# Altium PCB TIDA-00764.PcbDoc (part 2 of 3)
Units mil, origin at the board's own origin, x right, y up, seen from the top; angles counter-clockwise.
Board outline 6250 x 2150 mil, 4 copper layers (Top Layer, GND, VDD, Bottom Layer), stack 61.6 mil thick; 231 components, 137 nets, 687 pads, 247 vias.

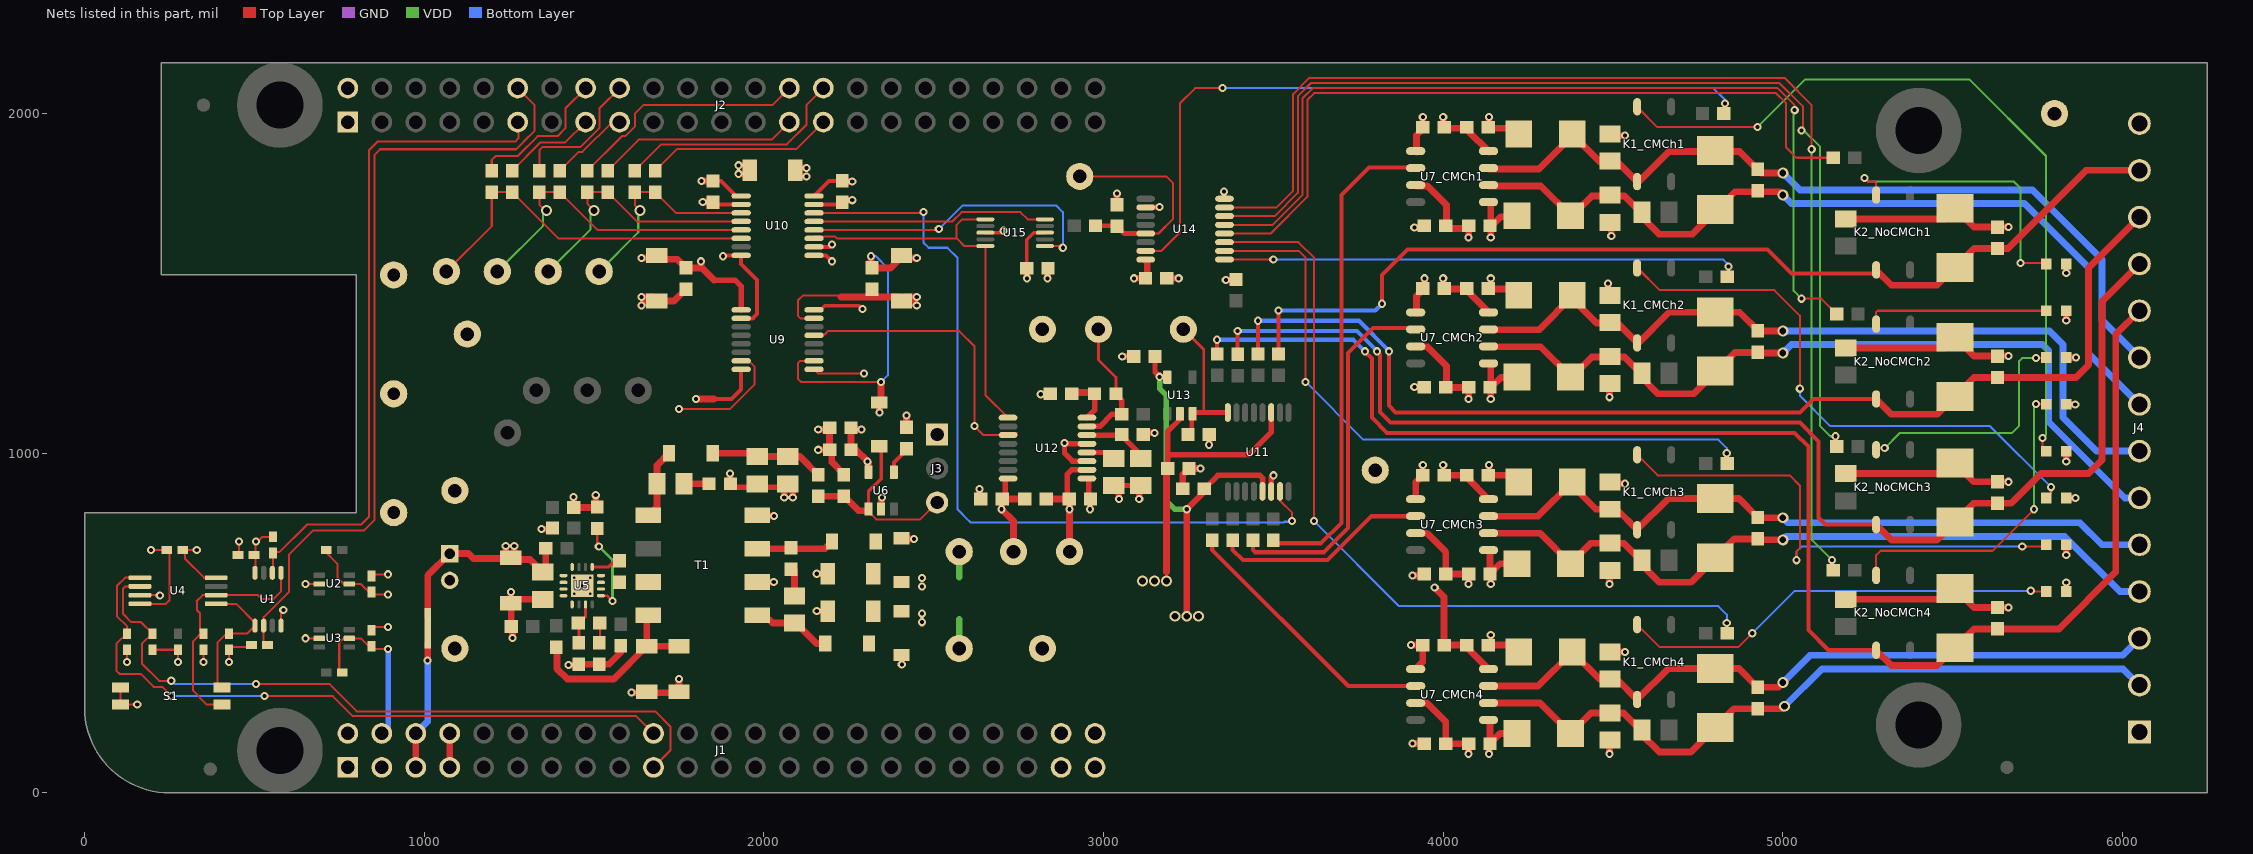
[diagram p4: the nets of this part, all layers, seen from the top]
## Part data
C1 C2 C3 C4: "CAP, CERM, 0.1 µF, 50 V, +/- 10%, X7R, 0402"
C5: "CAP, CERM, 1000 pF, 2000 V, +/- 10%, X7R, 1206_190"
C6: "CAP, AL, 47 µF, 35 V, +/- 20%, TH"
C7 C13 C14 C33 C34: "CAP, CERM, 22 µF, 10 V, +/- 10%, X7R, 1206"
C8 C18 C19 C47 C48: "CAP, CERM, 10 µF, 10 V, +/- 10%, X7R, 0805"
C9 C12: "CAP, CERM, 2.2 µF, 50 V, +/- 10%, X7R, 1206"
C10 C17 C35 C36 C37 C38 C49 C50 C51: "CAP, CERM, 0.1 µF, 16 V, +/- 10%, X7R, 0603"
C11 C23: "CAP, CERM, 15 pF, 50 V, +/- 5%, C0G/NP0, 0603"
C15 C16 C21: "CAP, CERM, 2.2 µF, 10 V, +/- 10%, X7R, 0603"
C20: "CAP, CERM, 0.033 µF, 50 V, +/- 10%, X7R, 0603"
C22: "CAP, CERM, 82 pF, 50 V, +/- 5%, C0G/NP0, 0603"
C24: "CAP, CERM, 0.01 µF, 16 V, +/- 10%, X7R, 0603"
C25_CMCh1 C25_CMCh2 C25_CMCh3 C25_CMCh4 C30_CMCh1 C30_CMCh2 C30_CMCh3 C30_CMCh4 C39 C44 C45: "CAP, CERM, 0.1 µF, 50 V, +/- 10%, X7R, 0603"
C26_CMCh1 C26_CMCh2 C26_CMCh3 C26_CMCh4 C31_CMCh1 C31_CMCh2 C31_CMCh3 C31_CMCh4 C40 C41 C46: "CAP, CERM, 1 µF, 16 V, +/- 10%, X7R, 0603"
C27_CMCh1 C27_CMCh2 C27_CMCh3 C27_CMCh4 C29_CMCh1 C29_CMCh2 C29_CMCh3 C29_CMCh4: "CAP, CERM, 1000 pF, 630 V, +/- 5%, X7R, 0805"
C28_CMCh1 C28_CMCh2 C28_CMCh3 C28_CMCh4 C32_NoCMCh1 C32_NoCMCh2 C32_NoCMCh3 C32_NoCMCh4: "CAP, CERM, 0.01 µF, 100 V, +/- 10%, X7R, 0603"
C42: "CAP, CERM, 100 pF, 50 V, +/- 5%, C0G/NP0, 0603"
C43: "CAP, CERM, 820 pF, 50 V, +/- 5%, C0G/NP0, 0603"
D1 D4: "Diode, Ultrafast, 100 V, 0.15 A, SOD-123"
D2 D3: "Diode, Zener, 16 V, 500 mW, SOD-123"
D5 D6: "Diode, Schottky, 30 V, 0.5 A, SOD-123"
D7_CMCh1 D7_CMCh2 D7_CMCh3 D7_CMCh4 D10_CMCh1 D10_CMCh2 D10_CMCh3 D10_CMCh4: "Diode, TVS, Bi, 160 V, 400 W, SMA"
D8_CMCh1 D8_CMCh2 D8_CMCh3 D8_CMCh4 D11_NoCMCh1 D11_NoCMCh2 D11_NoCMCh3 D11_NoCMCh4: "LED, Blue, SMD"
D9_CMCh1 D9_CMCh2 D9_CMCh3 D9_CMCh4 D12_NoCMCh1 D12_NoCMCh2 D12_NoCMCh3 D12_NoCMCh4: "Diode, TVS, Bi, 36 V, 600 W, SMB"
FID1 FID2 FID3: "Fiducial mark.  There is nothing to buy or mount."
J1 J2: "Female Connector, 2.54mm, 23x2, TH"
J3: "Header, 100mil, 3x1, Tin, TH"
J4: "Header (Shrouded), 3.5mm, 14x1, Tin, R/A, TH"
K1_CMCh1 K1_CMCh2 K1_CMCh3 K1_CMCh4 K2_NoCMCh1 K2_NoCMCh2 K2_NoCMCh3 K2_NoCMCh4: "Relay, SPST-NO (1 Form A), 0.1 A, 1.2 VDC, SMD"
Logo1: library part TI_Logo, "Texas Instrument Corporate Signature"
Logo2: library part Pb-Free
MH1 MH2 MH3 MH4: library part "Mounting Hole (Imperial) with Pads", "PCB Mounting Hole"
NT1: "Single point connection between nets."
R1 R2 R3 R4 R13 R14 R15: "RES, 47 k, 5%, 0.063 W, 0402"
R5 R6 R7 R8 R9 R10 R11 R12 R24 R33 R41 R42: "RES, 0, 5%, 0.1 W, 0603"
R16 R17: "RES, 6.65 k, 1%, 0.063 W, 0402"
R18 R26: "RES, 1.0 k, 5%, 0.125 W, 0805"
R19 R27: "RES, 10 k, 5%, 0.1 W, 0603"
R20: "RES, 220 k, 5%, 0.1 W, 0603"
R21: "RES, 16.2 k, 1%, 0.1 W, 0603"
R22: "RES, 75 k, 5%, 0.1 W, 0603"
R23: "RES, 10.0 k, 1%, 0.1 W, 0603"
R25: "RES, 240 k, 5%, 0.1 W, 0603"
R28_CMCh1 R28_CMCh2 R28_CMCh3 R28_CMCh4 R30_NoCMCh1 R30_NoCMCh2 R30_NoCMCh3 R30_NoCMCh4: "RES, 49.9, 1%, 0.1 W, 0603"
R29_CMCh1 R29_CMCh2 R29_CMCh3 R29_CMCh4 R31_NoCMCh1 R31_NoCMCh2 R31_NoCMCh3 R31_NoCMCh4: "RES, 200, 0.1%, 0.125 W, 0805"
R32 R34 R35 R36 R37 R38 R39 R40: "RES, 5.11 k, 1%, 0.1 W, 0603"
R43: "RES, 100 k, 5%, 0.1 W, 0603"
R44: "RES, 47 k, 5%, 0.1 W, 0603"
S1: "Switch, SPST, Off-On, 2 Pos, SMD"
SH-J1: "Shunt, 2.54mm, Gold, Black"
T1: "Transformer, 2.7 uH, SMT"
TP1 TP2 TP3: "TEST POINT.  No entry in BOM."
TP4 TP5 TP7 TP8: "Test Point, Miniature, Red, TH"
TP6 TP9 TP10 TP11 TP12 TP24: "Test Point, Miniature, Black, TH"
TP13 TP14 TP15 TP16 TP17 TP18 TP19 TP20 TP22 TP23 TP25: "Test Point, Miniature, Yellow, TH"
TP21: "Test Point, Miniature, Orange, TH"
U1: "Dual 2-Input Exclusive-OR Gate, DCT0008A"
U2 U3: "Single 3-Input Positive-OR Gate, DCK0006A"
U4: "256K I2C CMOS Serial EEPROM, TSSOP-8"
U5: "2.95V To 6V Input, 2W, Isolated DC/DC Converter with Integrated FETs, RTE0016C"
U6: "150-mA Low-noise Low-dropout Regulator With Shutdown, DBV0005A"
U7_CMCh1 U7_CMCh2 U7_CMCh3 U7_CMCh4: "High Common-Mode Voltage Difference Amplifier, D0008A"
U9 U10: "4242-VPK Small-Footprint and Low-Power Quad Channels Digital Isolators, DBQ0016A"
U11: "Fault-Protected, 8-Channel, Single-Ended Multiplexer, PW0016A"
U12: "SAR ADC with 16 Bits, Single Channel, 1MSPS, and Bipolar Inputs off +5 V Supply, PW0016A"
U13: "36-V, Precision, Rail-to-Rail Input/Output, Low Offset Voltage, Low Input Bias Current Op Amp with e-trim, DBV0005A"
U14: "8-Bit Shift Register With Output Registers, PW0016A"
U15: "DUAL 10-Ohm SPDT ANALOG SWITCH, DGS0010A"
ZZ1 ZZ2 ZZ3: library part AssemblyNote

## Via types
v1: diameter 24, hole 12, Top Layer to Bottom Layer, 201 vias
v2: diameter 39.37, hole 19.68, Top Layer to Bottom Layer, 24 vias
v3: diameter 32, hole 20, Top Layer to Bottom Layer, 17 vias
v4: diameter 19.68, hole 7.87, Top Layer to Bottom Layer, tented top, 5 vias

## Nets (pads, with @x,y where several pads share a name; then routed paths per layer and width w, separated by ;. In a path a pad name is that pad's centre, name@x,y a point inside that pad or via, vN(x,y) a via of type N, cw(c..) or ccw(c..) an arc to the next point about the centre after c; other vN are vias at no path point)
+5V: C6.1 C7.1 C8.2 C33.1 C35.1 C37.1 NT1.2 R19.2 R20.2 TP4.1 U5.1 U5.2 U5.16 U9.1 U9.7 U10.1 | length 1545.7
  Top Layer w6: v1@1750,1134.2 v1(1750,1130) 1899.29,1130 1972.45,1203.15 1972.45,1254.83 1955.21,1272.07 U9.7@1933.03,1272.07
  Top Layer w12: C37.1@1850.32,1801.5 1873.5,1801.5 1917.5,1757.5 U10.1@1933.03,1757.5
  Top Layer w16: 1853.31,1509.57 1915.43,1509.57 1933.03,1491.97 U9.1@1933.03,1422.07
  Top Layer w20: NT1.2@1010,520 1010,639.37 C6.1@1075,704.37 1130.63,704.37 1145,690 C7.1@1244.73,690 ; C7.1@1239.87,701.11 v1(1239.87,726.38) ; C7.1@1253.9,687.09 1311.81,687.09 C8.2@1348.9,650 ; C7.1@1264.87,698.06 v1(1264.87,726.38) ; v1(1344.87,776.38) R19.2@1373.78,776.38 ; C8.2@1357.4,658.5 R20.2@1357.4,720 ; v1(1640,1575) 1673.97,1575 1677.63,1571.34 1744.72,1571.34 C35.1@1770.32,1545.75 1817.13,1545.75 1853.31,1509.57 ; 1815,1547.88 v1(1815,1565) ; v1(1816.5,1801.5) C37.1@1850.32,1801.5
+5V_ISO: C15.1 C16.1 C34.1 C36.1 C38.1 C40.1 C49.1 C50.1 D5.2 R33.1 R43.2 TP8.1 U6.5 U9.10 U9.16 U10.10 U10.16 U12.16 U14.10 U14.16 U15.8 | length 2170.3
  Top Layer w6: U9.10@2147.6,1272.07 2107.5,1272.07 2100,1264.57 2100,1219.57 2110,1209.57 2227.32,1209.57 v1(2345,1209.57)
  Top Layer w10: U9.16@2147.6,1422.07 2167.07,1422.07 2179.25,1434.25 2280.75,1434.25 v1(2290,1425) ; C49.1@2773.5,1545 2773.5,1628.5 2794.37,1649.37 U15.8@2827.28,1649.37
  Top Layer w12: U10.10@2147.6,1607.5 2192.5,1607.5 v1(2200,1615) ; U10.16@2147.6,1757.5 2191.91,1801.81 C38.1@2230.32,1801.81
  Top Layer w16: C40.1@2710,873.5 U12.16@2710,925 ; U14.10@3123.86,1723.66 3163.66,1723.66 v1(3165,1725)
  Top Layer w20: C38.1@2232.13,1800 v1(2260,1800) ; C16.1@2256.5,1071.32 2256.5,1011.32 2270.33,1011.32 2305,976.65 v1(2305,975) 2307.91,972.09 U6.5@2307.91,944.13 ; C16.1@2257.8,1070.02 v1(2287.4,1070.02) ; C36.1@2315,1549.02 v1(2315,1580) ; C36.1@2318.27,1545.75 2372.68,1545.75 2401.93,1575 v1(2450,1575) ; v1(2340,1119.86) D5.2@2340,1149.47 2345,1154.47 v1(2345,1209.57) ; C40.1@2698.05,865 R33.1@2768.5,865 ; C40.1@2700,865 v1(2700,835) 2735,800 TP8.1@2735,710 ; v1(2775,1515) C49.1@2775,1543.5 ; v1(3090,1515) C50.1@3119.8,1515 ; U14.16@3125,1565.59 3128.5,1562.09 C50.1@3128.5,1506.3 ; v1(3360,1510) 3388.5,1510 R43.2@3390,1511.5
  Bottom Layer w6: v1(2315,1580) 2330,1580 2365,1545 2365,1229.57 v1(2345,1209.57)
+5V_JACK: J1.5 J1.6 NT1.1 | length 379.5
  Top Layer w20: J1.5@975,75 J1.6@975,175 ; v1(1010,390) NT1.1@1010,440
  Bottom Layer w20: J1.6@975,175 1010,210 v1(1010,390)
+5V_JACK_USB: J1.7 J1.8 | length 100
  Top Layer w20: J1.7@1075,75 J1.8@1075,175
+15V_ISO: C9.1 C30_CMCh1.2 C30_CMCh2.2 C30_CMCh3.2 C30_CMCh4.2 C31_CMCh1.1 C31_CMCh2.1 C31_CMCh3.1 C31_CMCh4.1 C44.1 C45.2 D1.1 D2.1 TP5.1 U7_CMCh1.7 U7_CMCh2.7 U7_CMCh3.7 U7_CMCh4.7 U11.13 U13.5 | length 2338.2
  Top Layer w6: C30_CMCh4.2@4074.76,144.51 C30_CMCh4.2@4075,144.28
  Top Layer w16: C44.1@3151.5,1285 3151.5,1238.5 v1(3165,1225) 3186.73,1225 U13.5@3187.6,1224.13 ; C45.2@3296.5,895 3336.5,935 3460,935 3468.11,926.89 U11.13@3468.11,887.4
  Top Layer w20: v3(3245,520) v1(3245,835) 3296.5,886.5 C45.2@3296.5,895 ; U7_CMCh4.7@3918.98,264.51 3951.75,264.51 4007.76,208.5 C31_CMCh4.1@4007.76,144.51 C30_CMCh4.2@4074.76,144.51 ; U7_CMCh3.7@3918.98,764.51 3951.75,764.51 4007.76,708.5 C31_CMCh3.1@4007.76,644.51 C30_CMCh3.2@4074.76,644.51 ; U7_CMCh2.7@3921.2,1313.23 3953.97,1313.23 4009.98,1257.22 4009.98,1193.23 C30_CMCh2.2@4076.98,1193.23 ; U7_CMCh1.7@3921.2,1786.5 3953.97,1786.5 4009.98,1730.49 C31_CMCh1.1@4009.98,1666.5 ; C31_CMCh1.1@4009.98,1661.5 C30_CMCh1.2@4076.98,1661.5 ; v1(4075,115) C30_CMCh4.2@4075,144.28 ; v1(4075,615) C30_CMCh3.2@4075,644.28 ; v1(4075,1160) 4075,1185.21 C30_CMCh2.2@4080,1190.21 ; v1(4075,1635) 4075,1658.48 C30_CMCh1.2@4080,1663.48
  VDD w16: v1(3165,1225) 3165,1190 3185,1170 3185,860 3210,835 v1(3245,835)
  VDD w20: TP5.1@2575,425 2575,510
  other v1: 2465.98,502.52 2465.98,527.52
  other v3: 3210,520 3280,520
-15V_ISO: C12.2 C25_CMCh1.1 C25_CMCh2.1 C25_CMCh3.1 C25_CMCh4.1 C26_CMCh1.2 C26_CMCh2.2 C26_CMCh3.2 C26_CMCh4.2 C39.2 D3.2 D4.2 TP7.1 U7_CMCh1.4 U7_CMCh2.4 U7_CMCh3.4 U7_CMCh4.4 U11.3 U13.2 | length 1895.9
  Top Layer w6: C25_CMCh2.1@4000,1489.69 C25_CMCh2.1@4004.98,1484.72 ; C25_CMCh1.1@4000.5,1962.46 4005.98,1956.99 C25_CMCh1.1@4008.48,1954.48
  Top Layer w16: v3(3150,623.78) v3@3155,623.78 ; C39.2@3188.5,955 3188.5,1063.5 3225,1100 U13.2@3225,1115.87 ; 3190,995 3427.09,995 3493.7,1061.61 U11.3@3493.7,1119.68
  Top Layer w20: 3185,650 3185,951.5 C39.2@3188.5,955 ; v1(3975,605) 4002.76,577.24 C25_CMCh4.1@4002.76,435 C26_CMCh4.2@4069.76,435 4069.76,428.29 U7_CMCh4.4@4133.54,364.51 ; C25_CMCh3.1@4000,937.76 v1(4000,965) ; v1(4000,1515) 4000,1488.74 C25_CMCh2.1@4005,1483.74 ; C25_CMCh1.1@4000,1961.96 v1(4000,1990) ; C25_CMCh3.1@4002.76,935 C26_CMCh3.2@4069.76,935 4069.76,928.29 U7_CMCh3.4@4133.54,864.51 ; C25_CMCh2.1@4004.98,1483.72 4071.98,1483.72 4071.98,1477.01 U7_CMCh2.4@4135.76,1413.23 ; C25_CMCh1.1@4004.98,1956.99 4005.98,1956.99 4071.98,1956.99 4071.98,1950.28 U7_CMCh1.4@4135.76,1886.5
  VDD w20: 2575,635 TP7.1@2575,710
  other v1: 2465.98,607.52 2465.98,632.52
  other v3: 3115,623.78 3185,623.78
"A0 / SER": R7.2 R8.2 TP18.1 U10.5 | length 952.7
  Top Layer w6: v3(1360,1715) 1360,1710 1338.68,1731.32 R8.2@1338.68,1768.5 R7.2@1398.68,1768.5 1509.68,1657.5 U10.5@1933.03,1657.5
  VDD w6: TP18.1@1215,1535 1350,1670 1350,1705 v3(1360,1715)
"A0 / SER_ISO": U10.12 U15.6 | length 930.5
  Top Layer w6: U10.12@2147.6,1657.5 2512.5,1657.5 v1(2515,1660) ; U15.6@2827.28,1610 2875,1610 v1(2880,1605)
  Bottom Layer w6: v1(2515,1660) 2585,1730 2860,1730 2880,1710 v1(2880,1605)
"A1 / R\C\L\R\": R9.2 R10.2 TP19.1 U10.4 | length 786.4
  Top Layer w6: v3(1500,1715) 1480,1735 R10.2@1480,1768.5 R9.2@1540,1768.5 1626,1682.5 U10.4@1933.03,1682.5
  VDD w6: TP19.1@1365,1535 1490,1660 1490,1705 v3(1500,1715)
"A1 / R\C\L\R\_ISO": U10.13 U15.10 | length 699.4
  Top Layer w6: U10.13@2147.97,1682.87 2555.22,1682.87 2582.35,1710 2755,1710 2776.26,1688.74 U15.10@2827.28,1688.74
A2: R11.2 R12.2 TP20.1 U10.3 | length 627.7
  Top Layer w6: v3(1635,1715) 1620,1730 R12.2@1620,1768.5 R11.2@1680,1768.5 1741,1707.5 U10.3@1933.03,1707.5
  VDD w6: TP20.1@1515,1535 1630,1650 1630,1710 v3(1635,1715)
A2_ISO: U10.14 U11.15 | length 2377
  Top Layer w6: U10.14@2147.6,1707.5 2467.5,1707.5 v1(2470,1710) ; U11.15@3519.29,887.4 3519.29,860.71 3555,825 v1(3555,800)
  Bottom Layer w6: v1(2470,1710) 2470,1620 2485,1605 2540,1605 2570,1575 2570,835 2605,800 2605.38,800 2609.25,796.13 3530.75,796.13 3532.87,798.25 3553.25,798.25 v1(3555,800)
AVDD: C41.1 R33.2 TP21.1 U12.2 | length 354
  Top Layer w16: C41.1@2893.5,865 2893.5,938.5 2906.02,951.02 U12.2@2951.14,951.02
  Top Layer w20: R33.2@2831.5,865 C41.1@2893.5,865 ; C41.1@2898.5,865 2900,863.5 v1(2900,835) TP21.1@2900,710
CAPE_A0: J2.12 R1.2 U1.2 | length 2336.2
  Top Layer w6: U1.2@527.22,473.95 527.22,517.22 562.25,552.25 562.53,552.25 596.28,586 596.28,586.28 602.02,592.02 602.02,702.02 672.13,772.13 821.9,772.13 852.87,803.1 852.87,1877.87 870,1895 1270.5,1895 1292.87,1917.38 ; U1.2@527.2,492.24 527.2,446.42 R1.2@538.62,435 ; J2.12@1275,2075 1325,2025 1325,1950 1292.87,1917.87
CAPE_A1: J2.11 R3.2 U1.6 | length 1966.8
  Top Layer w6: U1.6@555,649.96 R3.2@555,706.38 557.2,708.58 573.58,708.58 655,790 814.5,790 837.2,812.71 837.2,1892.2 862.2,1917.2 1267.43,1917.2 1277.2,1926.98 J2.11@1277.2,1977.2
CH_IN+1: C32_NoCMCh1.1 D12_NoCMCh1.2 J4.13 K2_NoCMCh1.3 R40.2 | length 2975.3
  Top Layer w12: R40.2@3515,1292.07 v1(3515,1420) ; v1(3820,1440) 3820,1525 3895,1600 4955,1600 5025.24,1529.76 K2_NoCMCh1.3@5275,1529.76
  Top Layer w20: K2_NoCMCh1.3@5275,1539.76 5320.21,1494.55 5454.24,1494.55 D12_NoCMCh1.2@5507,1547.31 5562.51,1602.82 C32_NoCMCh1.1@5632,1602.82 5662.82,1602.82 5892.87,1832.87 J4.13@6050.04,1832.87
  Bottom Layer w12: v1(3515,1420) 3800,1420 v1(3820,1440)
CH_IN+2: C32_NoCMCh2.1 D12_NoCMCh2.2 J4.12 K2_NoCMCh2.3 R39.2 | length 3342.1
  Top Layer w12: R39.2@3455,1292.07 v1(3455,1390) ; v1(3840,1300) 3840,1140 3860,1120 5050,1120 5089.76,1159.76 K2_NoCMCh2.3@5275,1159.76
  Top Layer w20: K2_NoCMCh2.3@5275,1159.76 5320.21,1114.55 5454.24,1114.55 D12_NoCMCh2.2@5507,1167.31 5562.51,1222.82 C32_NoCMCh2.1@5632,1222.82 5862.82,1222.82 5900,1260 5900,1545.04 J4.12@6050.04,1695.08
  Bottom Layer w12: v1(3455,1390) 3751.59,1390 3840,1301.59 v1(3840,1300)
CH_IN+3: C32_NoCMCh3.1 D12_NoCMCh3.2 J4.11 K2_NoCMCh3.3 R38.2 | length 3820.6
  Top Layer w12: R38.2@3395,1292.07 v1(3395,1360) ; v1(3805,1300) 3814.13,1290.87 3814.13,1120.87 3845,1090 5050,1090 5105,1035 5105,810 5125.24,789.76 K2_NoCMCh3.3@5275,789.76
  Top Layer w20: K2_NoCMCh3.3@5275,789.76 5320.21,744.55 5454.24,744.55 D12_NoCMCh3.2@5507,797.31 5562.51,852.82 C32_NoCMCh3.1@5632,852.82 5672.82,852.82 5760,940 5900,940 5940,980 5940,1447.24 J4.11@6050.04,1557.28
  Bottom Layer w12: v1(3395,1360) 3746.59,1360 3805,1301.59 v1(3805,1300)
CH_IN+4: C32_NoCMCh4.1 D12_NoCMCh4.2 J4.10 K2_NoCMCh4.3 R37.2 | length 4414.3
  Top Layer w12: R37.2@3334.02,1293.05 v1(3334.02,1334.02) ; v1@3770,1298.41 3790,1278.41 3790,1105 3835,1060 3850,1060 5034.87,1060.13 5075,1020 5075,480 5135.24,419.76 K2_NoCMCh4.3@5275,419.76
  Top Layer w20: K2_NoCMCh4.3@5275,419.76 5320.21,374.55 5454.24,374.55 D12_NoCMCh4.2@5507,427.31 5562.51,482.82 C32_NoCMCh4.1@5632,482.82 5812.82,482.82 5980,650 5980,1349.45 J4.10@6050.04,1419.49
  Bottom Layer w12: v1(3334.02,1334.02) 3735.98,1334.02 v1(3770,1300)
CH_V/C_SWITCH1: R30_NoCMCh1.2 U14.4 | length 2285.3
  Top Layer w6: U14.4@3356.14,1646.89 3491.89,1646.89 3600,1755 3600,2040 3620,2060 4980,2060 5010,2030 5010,1900 5040,1870 R30_NoCMCh1.2@5148.5,1870
CH_V/C_SWITCH2: R30_NoCMCh2.2 U14.5 | length 2735.8
  Top Layer w6: U14.5@3356.14,1672.48 3497.86,1672.48 3586.13,1760.75 3586.13,2045.75 3615.38,2075 4984.62,2075 5035,2024.62 v1(5035,2010) ; v1(5055,1455) 5113.5,1455 R30_NoCMCh2.2@5158.5,1410
  VDD w6: v1(5035,2010) 5032.13,2007.13 5032.13,1477.87 v1(5055,1455)
CH_V/C_SWITCH3: R30_NoCMCh3.2 U14.6 | length 3114.7
  Top Layer w6: U14.6@3356.14,1698.07 3503.83,1698.07 3572.25,1766.49 3572.25,2051.49 3610.76,2090 4989.62,2090 5059.62,2020 5059.62,1954.62 v1(5055,1950) ; R30_NoCMCh3.2@5155,1023.5 v1(5155,1050)
  VDD w6: v1(5055,1950) 5062.35,1950 5110,1902.35 5110,1080 5140,1050 v1(5155,1050)
CH_V/C_SWITCH4: R30_NoCMCh4.2 U14.7 | length 3483.2
  Top Layer w6: U14.7@3356.14,1723.66 3509.8,1723.66 3558.38,1772.24 3558.38,2057.24 3606.14,2105 5005,2105 5085,2025 v1(5085,1895) ; v1(5145,685) 5145,658.5 R30_NoCMCh4.2@5148.5,655
  VDD w6: v1(5085,1895) 5085,745 v1(5145,685)
CMCH_IN+1: C27_CMCh1.1 C28_CMCh1.1 D7_CMCh1.1 D9_CMCh1.2 J4.9 K1_CMCh1.3 U7_CMCh1.3 | length 2407.6
  Top Layer w20: U7_CMCh1.3@4135.76,1836.5 4281.73,1836.5 4382.22,1936.99 4462.22,1856.99 4493.48,1856.99 4513.24,1856.99 4573.48,1796.75 4665,1888.27 4803.48,1888.27 4872.97,1888.27 4928.48,1832.76 4936.24,1825 v3(5000,1825)
  Bottom Layer w20: v3(5000,1825) 5050,1775 5735,1775 5940,1570 5940,1391.73 J4.9@6050.04,1281.69
CMCH_IN+2: C27_CMCh2.1 C28_CMCh2.1 D7_CMCh2.1 D9_CMCh2.2 J4.7 K1_CMCh2.3 U7_CMCh2.3 | length 2353.3
  Top Layer w20: U7_CMCh2.3@4135.76,1363.23 4281.73,1363.23 4382.22,1463.72 4382.22,1452.78 4451.28,1383.72 4493.48,1383.72 4513.24,1383.72 4573.48,1323.48 4665,1415 4803.48,1415 4872.97,1415 C28_CMCh2.1@4928.48,1359.49 ; C28_CMCh2.1@4928.99,1360 v3(5000,1360)
  Bottom Layer w20: v3(5000,1360) 5785,1360 5825,1320 5825,1105 5923.9,1006.1 J4.7@6050.04,1006.1
CMCH_IN+3: C27_CMCh3.1 C28_CMCh3.1 D7_CMCh3.1 D9_CMCh3.2 J4.5 K1_CMCh3.3 U7_CMCh3.3 | length 2116.2
  Top Layer w20: U7_CMCh3.3@4133.54,814.51 4279.51,814.51 D7_CMCh3.1@4380,915 4380,905 4450,835 C27_CMCh3.1@4491.26,835 4511.02,835 K1_CMCh3.3@4571.26,774.76 4662.78,866.28 D9_CMCh3.2@4801.26,866.28 4870.75,866.28 C28_CMCh3.1@4926.26,810.77 4927.03,810 v3(5000,810)
  Bottom Layer w20: v3(5000,810) 5015,795 5875,795 5939.49,730.51 J4.5@6050.04,730.51
CMCH_IN+4: C27_CMCh4.1 C28_CMCh4.1 D7_CMCh4.1 D9_CMCh4.2 J4.3 K1_CMCh4.3 U7_CMCh4.3 | length 2143.4
  Top Layer w20: U7_CMCh4.3@4133.54,314.51 4279.51,314.51 D7_CMCh4.1@4380,415 4460,335 C27_CMCh4.1@4491.26,335 4511.02,335 K1_CMCh4.3@4571.26,274.76 4662.78,366.28 D9_CMCh4.2@4801.26,366.28 4870.75,366.28 C28_CMCh4.1@4926.26,310.77 4985.77,310.77 v3(5000,325) v3@5006.54,325
  Bottom Layer w20: v3(5000,325) 5080,405 6000.12,405 J4.3@6050.04,454.92
CMCH_IN-1: C28_CMCh1.2 C29_CMCh1.2 D9_CMCh1.1 D10_CMCh1.1 J4.8 R29_CMCh1.1 U7_CMCh1.2 | length 2487.8
  Top Layer w20: U7_CMCh1.2@4135.76,1786.5 4287.22,1786.5 4377.22,1696.5 4437.71,1756.99 4493.48,1756.99 4533.48,1756.99 4583.48,1706.99 4583.48,1696.99 4635.47,1645 4734.22,1645 4803.48,1714.26 4858.99,1769.77 4928.48,1769.77 4990.23,1769.77 v3(5000,1760)
  Bottom Layer w20: v3(5000,1760) 5025,1735 5711.65,1735 5900,1546.65 5900,1293.94 J4.8@6050.04,1143.9
CMCH_IN-2: C28_CMCh2.2 C29_CMCh2.2 D9_CMCh2.1 D10_CMCh2.1 J4.6 R29_CMCh2.1 U7_CMCh2.2 | length 2398.9
  Top Layer w20: U7_CMCh2.2@4135.76,1313.23 4287.22,1313.23 4377.22,1223.23 4437.71,1283.72 4493.48,1283.72 4533.48,1283.72 4583.48,1233.72 4583.48,1223.72 4632.2,1175 4737.5,1175 4803.48,1240.98 4858.99,1296.5 4928.48,1296.5 4929.98,1295 v3(5000,1295)
  Bottom Layer w20: v3(5000,1295) 5025,1320 5765,1320 5782.39,1302.61 5782.39,1092.61 6006.69,868.31 J4.6@6050.04,868.31
CMCH_IN-3: C28_CMCh3.2 C29_CMCh3.2 D9_CMCh3.1 D10_CMCh3.1 J4.4 R29_CMCh3.1 U7_CMCh3.2 | length 2157.8
  Top Layer w20: U7_CMCh3.2@4133.54,764.51 4285,764.51 D10_CMCh3.1@4375,674.51 4435.49,735 C29_CMCh3.2@4491.26,735 4531.26,735 4581.26,685 4581.26,675 4636.26,620 4728.99,620 D9_CMCh3.1@4801.26,692.27 4856.77,747.78 C28_CMCh3.2@4926.26,747.78 4929.04,745 v3(5000,745)
  Bottom Layer w20: v3(5000,745) 5010,755 5830,755 5992.28,592.72 J4.4@6050.04,592.72
CMCH_IN-4: C28_CMCh4.2 C29_CMCh4.2 D9_CMCh4.1 D10_CMCh4.1 J4.2 R29_CMCh4.1 U7_CMCh4.2 | length 2153.6
  Top Layer w20: U7_CMCh4.2@4133.54,264.51 4285,264.51 D10_CMCh4.1@4375,174.51 4435.49,235 C29_CMCh4.2@4491.26,235 4531.26,235 4581.26,185 4581.26,175 4636.26,120 4728.99,120 D9_CMCh4.1@4801.26,192.27 4856.77,247.78 C28_CMCh4.2@4926.26,247.78 4997.78,247.78 v3(5005,255)
  Bottom Layer w20: v3(5005,255) 5115,365 6002.17,365 J4.2@6050.04,317.13
CMCH_OUT1: R36.2 U7_CMCh1.6 | length 1451.1
  Top Layer w12: R36.2@3496.63,742.05 3503.68,735 3640,735 3700,795 3700,1760 3781.5,1841.5 U7_CMCh1.6@3921.2,1841.5
CMCH_OUT2: R35.2 U7_CMCh2.6 | length 1087.4
  Top Layer w12: R35.2@3440,743.5 3440,715 3446.51,708.49 3648.49,708.49 3719.87,779.87 3719.87,1294.87 3793.23,1368.23 U7_CMCh2.6@3921.2,1368.23
CMCH_OUT3: R34.2 U7_CMCh3.6 | length 633.6
  Top Layer w12: R34.2@3380,743.5 3380,715 3410,685 3660,685 3789.51,814.51 U7_CMCh3.6@3918.98,814.51
CMCH_OUT4: R32.2 U7_CMCh4.6 | length 793.4
  Top Layer w12: R32.2@3320,743.5 3320,715 3720.49,314.51 U7_CMCh4.6@3918.98,314.51
CMCH_V/C_SWITCH1: R28_CMCh1.2 U14.15 | length 2182.4
  Top Layer w6: U14.15@3123.86,1595.71 3170.71,1595.71 3225,1650 3225,2030 3270,2075 v1(3350,2075) ; v1(4830,2030) 4830,2001.5 R28_CMCh1.2@4831.5,2000
  Bottom Layer w6: v1(3350,2075) 4795,2075 4830,2040 v1(4830,2030)
CMCH_V/C_SWITCH2: R28_CMCh2.2 U14.1 | length 1526.4
  Top Layer w6: U14.1@3356.14,1570.12 v1(3499.88,1570.12) ; R28_CMCh2.2@4836.5,1520 4840,1523.5 v1(4840,1550)
  Bottom Layer w6: v1@3500,1570 4825,1570 4840,1555 v1(4840,1550)
CMCH_V/C_SWITCH3: R28_CMCh3.2 U14.2 | length 1978.8
  Top Layer w6: U14.2@3356.14,1595.71 3574.29,1595.71 3595,1575 v1(3595,1210) ; v1(4835,1000) 4836.5,998.5 R28_CMCh3.2@4836.5,970
  Bottom Layer w6: v1(3595,1210) 3765,1040 4810,1040 4835,1015 v1(4835,1000)
CMCH_V/C_SWITCH4: R28_CMCh4.2 U14.3 | length 2442.6
  Top Layer w6: U14.3@3356.14,1621.3 3573.7,1621.3 3620,1575 v1(3620,800) ; v1(4835,500) 4836.5,498.5 R28_CMCh4.2@4836.5,470
  Bottom Layer w6: v1(3620,800) 3870,550 4810,550 4835,525 v1(4835,500)
CONVST/C\S\_ISO: U9.13 U12.11 | length 874
  Top Layer w6: U9.13@2147.6,1347.07 2150.53,1350 2180,1350 2190,1360 2226.89,1360 2227.32,1359.57 2575.43,1359.57 2620,1315 v1(2620,1080) 2646.61,1053.39 U12.11@2718.86,1053.39 2718.86,1059.24 2745.73,1059.24
DGND: C1.2 C2.2 C3.2 C4.2 C5.2 C6.2 C7.2 C8.1 C13.2 C14.2 C17.1 C22.1 C33.2 C35.2 C37.2 J1.1 J1.2 J1.43 J1.44 J1.45 J1.46 J2.1 J2.2 R22.1 R23.1 R25.1 R27.1 S1.1 S1.2 TP2.1 TP3.1 TP6.1 TP9.1 U1.4 U2.2 U3.2 U4.4 U4.7 U5.3 U5.4 U5.5 U5.17 U9.2 U9.8 U10.2 U10.8 | length 2159.8
  Top Layer w6: S1.1@105,310 S1.2@105,260 v1(155,260) v1@160.03,260 ; U4.7@162.8,582.2 212.2,582.2 220,590 221.35,588.65 v1(221.35,581.35) ; C4.2@288.62,715 295,708.65 295,690 351.61,633.39 U4.4@387.2,633.39 ; C4.2@296.53,715 v1(330,715) ; C1.2@455,693.62 v1(455,740) ; U1.4@578.39,492.37 578.39,528.51 585,535.13 v1(585,538.17) ; v1(649.98,614.99) U2.2@690.71,615 ; v1(650.73,455.01) U3.2@691.45,455.02 ; C3.2@845,478.64 854.9,488.52 v1(893.52,488.52) ; C2.2@845,638.62 849.9,643.52 v1@888.25,643.52 ; R23.1@1255.91,490 R23.1@1256.11,490 ; C22.1@1449.73,376.38 1454.73,381.38 C22.1@1456.11,380 ; R22.1@1453.9,847.8 R22.1@1454.87,848.77
  Top Layer w12: 1853.31,1159.57 1905,1159.57 1933.03,1187.6 U9.8@1933.03,1247.07 ; C37.2@1866.32,1732.5 U10.2@1933.03,1732.5 ; v1(1880,1580) 1882.5,1582.5 U10.8@1933.03,1582.5 1933.03,1557.06 1980,1510.09 1980,1410 1967.07,1397.07 U9.2@1933.03,1397.07
  Top Layer w20: C7.2@1254.87,570.52 v1(1254.87,591.38) ; R23.1@1256.11,490 C7.2@1256.11,569.29 ; C7.2@1256.81,570 C8.1@1348.9,570 ; v1(1259.87,456.38) R23.1@1259.87,486.03 ; v1(1424.87,376.38) C22.1@1449.73,376.38 ; R22.1@1439.87,840.52 v1(1439.87,871.38) ; R22.1@1440.4,840 1507.4,840 C17.1@1508.9,841.5 ; C22.1@1457.25,378.86 1544.65,378.86 1578.55,412.76 R25.1@1578.55,433.31 ; C17.1@1504.87,845.52 v1(1504.87,876.38) ; v1(1610,295) 1746.93,295 C14.2@1750,298.07 v1(1750,335) ; v1(1640,1435) 1653.07,1448.07 C33.2@1685,1448.07 1735.63,1448.07 C35.2@1770.32,1482.76 ; v1(1640,1460) C33.2@1673.07,1460 ; v1(1800,1160) 1852.88,1160 ; v1(1820,1740) C37.2@1838.82,1740 ; v1(1925,1822.64) C5.2@1948.07,1822.64 ; v1(1925,1847.64) C5.2@1943.07,1847.64
  other v1: 893.52,643.52
  other v4: 1441.38,586.38 1488.62,586.38 1465,610 1441.38,633.62 1488.62,633.62
DVDD: C1.1 C2.1 C3.1 C4.1 J1.3 J1.4 R1.1 R2.1 R3.1 R4.1 R13.1 R14.1 R15.1 R16.1 R17.1 TP1.1 U1.8 U2.5 U3.5 U4.8 | length 1522.4
  Top Layer w6: v1(125,385) R17.1@125.01,421.39 ; U4.8@162.8,556.61 238.86,556.61 249.87,567.63 249.87,715.01 C4.1@241.38,715 ; v1(195,715) C4.1@233.52,715.01 ; v1@275.01,377.89 R15.1@275.01,421.39 ; v1@350.02,377.89 R13.1@350.02,421.39 ; v1@425.02,377.89 R14.1@425.02,421.39 ; R14.1@425.02,429.27 477.77,429.27 R1.1@491.38,442.87 ; U1.8@503.62,649.89 503.62,700 503.62,733.62 523.62,753.62 R3.1@555,753.62 ; R2.1@703.52,715.01 745,673.53 745,633.25 749.69,628.57 758.38,619.84 763.24,615.01 813.52,615.01 845.02,583.52 v1(893.52,583.52) v1@895.02,585.01 ; R4.1@758.62,355 749.7,363.92 749.7,441.48 763.24,455.02 U3.5@779.31,455.02 813.52,455.02 845.02,423.52 v1(893.52,423.52)
  Top Layer w8: R16.1@200.01,421.39 R15.1@275.01,421.39
  Bottom Layer w16: J1.4@875,175 893.52,193.52 v1(893.52,423.52)
  other v1: 275,385 350,385 425,385 505,740
GND_ISO: C5.1 C9.2 C12.1 C15.2 C16.2 C18.2 C19.1 C21.2 C23.1 C24.2 C25_CMCh1.2 C25_CMCh2.2 C25_CMCh3.2 C25_CMCh4.2 C26_CMCh1.1 C26_CMCh2.1 C26_CMCh3.1 C26_CMCh4.1 C27_CMCh1.2 C27_CMCh2.2 C27_CMCh3.2 C27_CMCh4.2 C29_CMCh1.1 C29_CMCh2.1 C29_CMCh3.1 C29_CMCh4.1 C30_CMCh1.1 C30_CMCh2.1 C30_CMCh3.1 C30_CMCh4.1 C31_CMCh1.2 C31_CMCh2.2 C31_CMCh3.2 C31_CMCh4.2 C32_NoCMCh1.2 C32_NoCMCh2.2 C32_NoCMCh3.2 C32_NoCMCh4.2 C34.2 C36.2 C38.2 C39.1 C40.2 C41.2 C43.2 C44.2 C45.1 C46.2 C47.1 C48.1 C49.2 C50.2 C51.2 D2.2 D3.1 D7_CMCh1.2 D7_CMCh2.2 D7_CMCh3.2 D7_CMCh4.2 D8_CMCh1.2 D8_CMCh2.2 D8_CMCh3.2 D8_CMCh4.2 D10_CMCh1.2 D10_CMCh2.2 D10_CMCh3.2 D10_CMCh4.2 D11_NoCMCh1.2 D11_NoCMCh2.2 D11_NoCMCh3.2 D11_NoCMCh4.2 D12_NoCMCh1.1 D12_NoCMCh2.1 D12_NoCMCh3.1 D12_NoCMCh4.1 J3.1 J4.1 J4.14 R31_NoCMCh1.1 R31_NoCMCh2.1 R31_NoCMCh3.1 R31_NoCMCh4.1 R42.2 T1.5 T1.7 TP10.1 TP11.1 TP12.1 TP24.1 U6.2 U7_CMCh1.1 U7_CMCh1.5 U7_CMCh2.1 U7_CMCh2.5 U7_CMCh3.1 U7_CMCh3.5 U7_CMCh4.1 U7_CMCh4.5 U9.9 U9.15 U10.9 U10.15 U11.14 U12.1 U12.3 U12.5 U14.8 U15.3 | length 6913.6
  Top Layer w6: U9.9@2147.6,1247.07 2160.1,1234.57 v1(2295,1234.57) ; U9.15@2147.6,1397.07 2107.5,1397.07 2100,1404.57 2100,1449.57 2115.43,1465 2221.89,1465 2227.32,1459.57 ; C16.2@2184.47,1070.02 C16.2@2187.93,1066.56 ; C36.2@2330.63,1470.2 2340,1460.83 ; U6.2@2345.63,830.87 U6.2@2347.72,832.95 ; U11.14@3493.7,887.4 U11.14@3495,888.7 ; C25_CMCh1.2@3940,1958.97 C25_CMCh1.2@3941.98,1956.99 ; C26_CMCh4.1@4132.76,435 C26_CMCh4.1@4136.26,438.5 ; C26_CMCh3.1@4132.76,935 C26_CMCh3.1@4135,937.24 ; C30_CMCh4.1@4135,141.76 C30_CMCh4.1@4137.76,144.51 ; C26_CMCh2.1@4134.98,1483.72 C26_CMCh2.1@4138.48,1487.22
  Top Layer w10: U15.3@2652.09,1649.37 2699.37,1649.37 v1(2705,1655)
  Top Layer w12: U10.9@2147.6,1582.5 2182.5,1582.5 v1(2200,1565) ; U10.15@2147.6,1732.5 2224,1732.5 C38.2@2230.32,1738.82
  Top Layer w16: C23.1@1911.5,900 C19.1@2060,900 ; U12.3@2951.14,976.61 2908.39,976.61 2885,1000 v1(2885,1030) 2887.2,1027.8 U12.5@2951.14,1027.8 ; C41.2@2956.5,865 U12.1@2956.5,920.08 ; v1(2960,835) C41.2@2960,863.5 ; C48.1@3035,905 C47.1@3105,905 ; U14.8@3355,1750.39 v1(3355,1770) ; U11.14@3493.7,887.4 3493.7,928.7 v1(3500,935)
  Top Layer w20: C23.1@1900,911.5 v1(1900,940) ; T1.7@1980.04,620.98 v1(2029.02,620.98) ; T1.5@1992.09,815 v1(2030,815) ; v1(2060,870) C19.1@2060,900 ; v1(2085,870) C19.1@2085,895 ; C5.1@2099.29,1840 v1(2125,1840) ; C5.1@2109.57,1815 v1(2125,1815) ; v1(2155.59,535) C9.2@2186.12,535 ; v1(2155.59,645) C12.1@2186.12,645 ; v1(2160,1010.02) 2192.2,1010.02 2200,1002.22 2200,974.21 C21.2@2237.72,936.5 ; v1(2160,1070.02) 2184.47,1070.02 C16.2@2189.8,1070.02 ; C15.2@2193.5,1011.32 C16.2@2193.5,1071.32 ; 2227.32,1459.57 C34.2@2395.87,1459.57 ; C38.2@2236.5,1745 v1(2260,1745) ; U6.2@2345.32,835.87 2345.32,867.4 2347.72,869.8 v1(2347.72,870) ; C34.2@2405,1448.07 2436.93,1448.07 v1(2450,1435) ; v1(2405.98,377.52) D2.2@2405.98,408.05 ; D3.1@2410.98,747.52 v1(2441.52,747.52) ; C34.2@2415.67,1460 v1@2445,1460 ; C24.2@2420,1080.3 v1(2420,1111.09) ; C40.2@2635,868.5 v1(2635,895) ; v1(2815,1173.54) R42.2@2843.5,1173.54 ; v1(2835,1515) C49.2@2835,1543.5 ; C48.1@3035,905 3045,895 v1(3045,865) ; C51.2@3039.68,1731.18 v1@3039.68,1764.68 ; v1(3055,1285) C44.2@3088.5,1285 ; v1(3105,865) C47.1@3105,900 ; C46.2@3121.5,1060 v1(3150,1060) ; C50.2@3186.5,1515 v1(3221.26,1515) ; C45.1@3233.5,895 3233.5,937.01 C39.1@3251.5,955 v1(3285,955) ; v1(3310,1025) 3311.5,1026.5 C43.2@3311.5,1055 ; v1(3905,435) C25_CMCh4.2@3939.76,435 3939.76,385.3 U7_CMCh4.5@3918.98,364.51 ; v1(3910,145) C31_CMCh4.2@3944.28,145 ; v1(3910,640) C31_CMCh3.2@3940.25,640 ; v1(3915,1195) C31_CMCh2.2@3945.21,1195 ; v1(3915,1665) C31_CMCh1.2@3945.48,1665 ; U7_CMCh3.5@3918.98,864.51 3918.98,914.21 C25_CMCh3.2@3939.76,935 ; U7_CMCh2.5@3921.2,1413.23 3921.2,1462.93 C25_CMCh2.2@3941.98,1483.72 ; U7_CMCh1.5@3921.2,1886.5 3921.2,1936.2 C25_CMCh1.2@3941.98,1956.99 ; C25_CMCh3.2@3940,935.24 v1(3940,965) ; C25_CMCh1.2@3940,1958.97 v1(3940,1990) ; C25_CMCh2.2@3945,1486.73 v1(3945,1515) ; C26_CMCh4.1@4132.76,435 4202.52,435 D7_CMCh4.2@4222.52,415 ; C26_CMCh3.1@4132.76,935 4202.52,935 D7_CMCh3.2@4222.52,915 ; U7_CMCh4.1@4133.54,214.51 4137.76,210.3 C30_CMCh4.1@4137.76,144.51 4167.76,174.51 D10_CMCh4.2@4217.52,174.51 ; U7_CMCh3.1@4133.54,714.51 4137.76,710.3 C30_CMCh3.1@4137.76,644.51 4167.76,674.51 D10_CMCh3.2@4217.52,674.51 ; v1(4135,115) C30_CMCh4.1@4135,141.76 ; C26_CMCh3.1@4135,937.24 v1(4135,965) ; C26_CMCh2.1@4134.98,1483.72 4204.74,1483.72 D7_CMCh2.2@4224.74,1463.72 ; v1(4135,1990) 4135,1957.01 4204.74,1956.99 D7_CMCh1.2@4224.74,1936.99 ; U7_CMCh2.1@4135.76,1263.23 4139.98,1259.02 4139.98,1193.23 4169.98,1223.23 D10_CMCh2.2@4219.74,1223.23 ; U7_CMCh1.1@4135.76,1736.5 4139.98,1732.29 C30_CMCh1.1@4139.98,1666.5 ; C26_CMCh4.1@4140,442.24 v1(4140,465) ; v1(4140,615) C30_CMCh3.1@4140,642.27 ; v1(4140,1160) C30_CMCh2.1@4140,1193.2 ; C26_CMCh2.1@4140,1488.74 v1(4140,1515) ; v1(4140,1635) C30_CMCh1.1@4140,1666.48 ; D10_CMCh1.2@4219.74,1696.5 4169.98,1696.5 C30_CMCh1.1@4139.98,1666.5 ; C27_CMCh2.2@4485,1472.2 v1(4485,1500) ; v1(4490,115) C29_CMCh4.1@4490,153.74 ; v1(4490,615) C29_CMCh3.1@4490,653.74 ; v1(4490,1165) C29_CMCh2.1@4490,1200.24 ; C27_CMCh4.2@4491.26,415 v1(4535,415) ; v1(4495,1640) C29_CMCh1.1@4495,1675.47 ; C27_CMCh1.2@4495.47,1935 v1(4535,1935) ; C27_CMCh3.2@4496.26,910 v1(4535,910) ; R31_NoCMCh4.1@5185,570 5475.68,570 D12_NoCMCh4.1@5507,601.32 5562.51,545.81 C32_NoCMCh4.2@5632,545.81 v1(5664.19,545.81) ; R31_NoCMCh3.1@5185,940 5475.68,940 D12_NoCMCh3.1@5507,971.32 5562.51,915.81 C32_NoCMCh3.2@5632,915.81 v1(5664.19,915.81) ; R31_NoCMCh2.1@5185,1310 5475.68,1310 D12_NoCMCh2.1@5507,1341.32 5562.51,1285.81 C32_NoCMCh2.2@5632,1285.81 v1(5664.19,1285.81) ; R31_NoCMCh1.1@5185,1690 5475.68,1690 D12_NoCMCh1.1@5507,1721.32 5562.51,1665.81 C32_NoCMCh1.2@5632,1665.81 v1(5664.19,1665.81) ; D8_CMCh4.2@5834.53,592.72 v1(5834.53,619.53) ; v1(5834.53,700.47) D8_CMCh3.2@5834.53,730.51 ; D8_CMCh2.2@5834.53,868.32 v1(5861.68,868.32) ; v1(5834.53,975.47) D8_CMCh1.2@5834.53,1006.11 ; D11_NoCMCh4.2@5834.53,1143.9 v1(5861.1,1143.9) ; D11_NoCMCh3.2@5834.53,1281.69 v1(5863.31,1281.69) ; v1(5834.53,1390.47) D11_NoCMCh2.2@5834.53,1419.49 ; v1(5834.53,1530.47) D11_NoCMCh1.2@5834.53,1557.28
  GND w6: v1(4535,415) v1@4540,415
  other v1: 2450,1460 3040,1765
I2C_A0: R14.2 S1.4 U1.1 U4.1 | length 404.3
  Top Layer w6: U4.1@387.2,556.61 446.12,556.63 U1.1@501.63,501.12 ; S1.4@405,310 391.43,323.57 391.43,442.92 R14.2@421.08,472.57 ; R14.2@425.02,468.64 478.01,468.64 U1.1@501.61,492.24
I2C_A1: R13.2 S1.3 U1.5 U4.2 | length 703.3
  Top Layer w6: R13.2@340.02,476.51 340.02,528.16 330.88,537.29 330.88,564.12 330,565 347.2,582.2 U4.2@377.23,582.2 ; R13.2@350.02,476.51 318.44,444.94 318.44,301.56 360,260 S1.3@405,260 ; U4.2@379.44,580 U4.2@377.23,582.2 ; U1.5@578.4,638.91 578.4,593.4 555.13,570.13 522.63,570.13 510.55,582.2 U4.2@387.2,582.2 U4.2@377.23,582.2
I2C_CLK: J1.19 R16.2 U4.6 | length 2121.3
  Top Layer w6: U4.6@162.8,607.8 119.13,607.8 112.87,601.54 112.87,527.4 137.65,502.62 166.03,502.62 199.28,469.37 R16.2@200.01,468.64 ; R16.2@200.01,476.51 200.01,470.11 168.44,438.54 168.44,380.96 219.7,329.7 254.7,329.7 v1(255,330) ; v1(505,320) 721.1,320 801.1,240 1680,240 1725,195 1725,125 J1.19@1675,75
  Bottom Layer w6: v1(255,330) 265,320 v1(505,320)
I2C_SDA: J1.20 R17.2 U4.5 | length 2001
  Top Layer w6: U4.5@152.81,633.4 119.46,633.4 95,608.94 95,520 125.01,489.98 125.01,470.11 93.44,438.54 93.44,359.34 102.66,350.13 164.78,350.13 203.08,311.83 228.17,311.83 v1(255,285) ; v1(530,285) 730.82,285 789.82,226 1624,226 J1.20@1675,175
  Bottom Layer w6: v1(255,285) v1(530,285)
IN1+IN2: R5.2 R6.2 TP17.1 U10.6 | length 1079.6
  Top Layer w6: TP17.1@1065,1535 1198.7,1668.7 R6.2@1198.7,1768.5 R5.2@1258.7,1768.5 1394.7,1632.5 U10.6@1933.03,1632.5
IN1+IN2_ISO: U10.11 U12.9 U15.1 U15.5 | length 1185.8
  Top Layer w6: U10.11@2147.6,1632.5 2147.6,1637.87 2209.47,1637.87 2214.85,1632.5 2567.5,1632.5 ; U15.1@2652.09,1688.74 2583.74,1688.74 2567.5,1672.5 2567.5,1632.5 ; U12.9@2718.86,1104.57 2652.09,1171.34 U15.5@2652.09,1610 2590,1610 2567.5,1632.5
NetC10_1: C10.1 T1.2 U5.10 U5.11 U5.12
NetC10_2: C10.2 U5.13 | length 87.7
  Top Layer w10: U5.13@1494.53,665.12 1543.61,665.12 1561.37,682.87 C10.2@1574.87,682.87
NetC11_1: C11.1 R18.1 | length 72.6
  Top Layer w20: R18.1@2090,582.99 C11.1@2090,655.57
NetC11_2: C11.2 D4.1 T1.6 | length 229.2
  Top Layer w20: T1.6@1980.04,719.02 2179.55,719.02 D4.1@2200.53,740
NetC13_1: C13.1 C14.1 R21.1 T1.1 | length 568.9
  Top Layer w20: R21.1@1388.9,428.5 1391.15,426.26 1391.15,365.1 1421.25,335 1558.07,335 C13.1@1655,431.93 ; T1.1@1659.96,522.95 1655,517.99 C13.1@1655,431.93 ; C14.1@1750,431.93 C13.1@1655,431.93
NetC17_2: C17.2 U5.9 | length 274.9
  Top Layer w8: C17.2@1508.9,778.5 1508.9,730 v1(1513.9,725) ; U5.9@1520.12,580.47 1538.43,580.47 v1(1553.9,565) v1@1553.9,567.52
  VDD w8: v1(1513.9,725) 1553.9,685 v1(1553.9,565)
NetC18_1: C18.1 C19.2 D6.1 R24.1 | length 336.8
  Top Layer w20: D6.1@1849.47,1000 1970,1000 C18.1@1980,990 C19.2@2070,990 2106.5,990 R24.1@2160,936.5
NetC20_1: C20.1 C22.2 U5.7 | length 119.4
  Top Layer w8: C22.2@1455.75,443.35 1455.75,498.7 1474.84,517.79 U5.7@1474.84,554.88
NetC20_2: C20.2 R27.2 | length 59.6
  Top Layer w6: R27.2@1518.74,443.35 1517.25,441.85 1517.25,497.2 C20.2@1518.74,498.7
NetC21_1: C21.1 D5.1 J3.3 R24.2 U6.1 | length 610
  Top Layer w6: U6.1@2307.91,835.87 2307.91,830.87 2307.91,827.4 2330.32,805 2460,805 J3.3@2510,855
  Top Layer w10: U6.1@2307.91,835.87 2307.91,887.91 2345,925 D5.1@2345,1020
  Top Layer w20: R24.2@2160,873.5 C21.1@2235.67,873.5 ; C21.1@2234.02,875.16 C21.1@2235.67,873.5 ; C21.1@2237.72,873.5 C21.1@2235.67,873.5 ; U6.1@2307.91,830.87 2278.31,830.87 C21.1@2235.67,873.5
NetC23_2: C23.2 R26.1 | length 73.5
  Top Layer w20: R26.1@1765,910 C23.2@1838.5,910
NetC24_1: C24.1 U6.4 | length 84.8
  Top Layer w12: U6.4@2382.72,944.13 2382.72,972.72 2412.72,1002.72 2412.72,1006.22 C24.1@2420,1013.5
NetC42_1: C42.1 R41.1 TP23.1 U12.7 | length 395.7
  Top Layer w8: TP23.1@2985,1365 2985,1275 3036.5,1223.5 C42.1@3036.5,1173.54
  Top Layer w16: U12.7@2951.14,1078.98 2988.98,1078.98 3025,1115 R41.1@3053.5,1115 3053.5,1156.54 C42.1@3036.5,1173.54
NetC42_2: C42.2 R42.1 U12.8 | length 136.7
  Top Layer w16: U12.8@2951.14,1104.57 2973.5,1126.93 C42.2@2973.5,1175
  Top Layer w20: R42.1@2911.5,1178.54 C42.2@2968.5,1178.54
NetC43_1: C43.1 TP22.1 U11.8 U13.3 | length 444.2
  Top Layer w8: TP22.1@3235,1365 3295,1305 3295,1120
  Top Layer w14: C43.1@3260,1051.5 3260,1120 3260.32,1119.68 U11.8@3365.75,1119.68
NetC46_1: C46.1 C47.2 U12.6 | length 181.1
  Top Layer w16: U12.6@2951.14,1053.39 3051.89,1053.39 C47.2@3105,1000.28 ; C47.2@3105,985 C47.2@3105,990.28
NetC48_2: C48.2 U12.4 | length 76.8
  Top Layer w16: U12.4@2951.14,1002.2 C48.2@3017.8,1002.2 ; C48.2@3017.8,992.2 C48.2@3025,985
NetC51_1: C51.1 R44.2 TP25.1 U14.13 | length 653.5
  Top Layer w6: TP25.1@2930,1815 3185,1815 3205,1795 3205,1690 3161.89,1646.89 U14.13@3123.86,1646.89
  Top Layer w14: R44.2@2971.18,1669.68 C51.1@3028.19,1669.68 ; C51.1@3028.19,1679.68 C51.1@3039.68,1668.19 3060.98,1646.89 U14.13@3123.86,1646.89
NetD1_2: D1.2 R18.2 T1.8 | length 234.9
  Top Layer w20: T1.8@1980.04,522.95 2002.05,522.95 2025,500 R18.2@2090,500 2095,500 2155,440 D1.2@2180.53,440
NetD6_2: D6.2 R26.2 T1.4 | length 208
  Top Layer w20: T1.4@1659.96,817.05 1685,842.09 R26.2@1685,910 1685,964.47 D6.2@1720.53,1000
NetD8_CMCh1_1: D8_CMCh1.1 K1_CMCh1.2 | length 2253.8
  Top Layer w6: K1_CMCh1.2@4573.48,2017.22 4630.7,1960 v1(4925,1960) ; v1(5765,1045) 5765,1016.59 D8_CMCh1.1@5775.48,1006.11
  VDD w6: v1(4925,1960) 5065,2100 5550,2100 5775,1875 5775,1055 v1(5765,1045)
NetD8_CMCh2_1: D8_CMCh2.1 K1_CMCh2.2 | length 1658.6
  Top Layer w6: K1_CMCh2.2@4573.48,1543.95 4637.43,1480 4975,1480 5050,1405 v1(5050,1190) ; D8_CMCh2.1@5775.48,868.32 5790,882.84 v1(5790,900)
  Bottom Layer w6: v1(5050,1190) 5050,1170 5140,1080 5610,1080 v1(5790,900)
NetD8_CMCh3_1: D8_CMCh3.1 K1_CMCh3.2 | length 1509.2
  Top Layer w6: K1_CMCh3.2@4571.26,995.24 4631.5,935 5020,935 5050,905 5050,720 5040,710 v1(5040,685) ; v1(5705,725) 5769.96,725 D8_CMCh3.1@5775.48,730.51
  Bottom Layer w6: v1(5040,685) 5040,710 5055,725 v1(5705,725)
NetD8_CMCh4_1: D8_CMCh4.1 K1_CMCh4.2 | length 1300.5
  Top Layer w6: K1_CMCh4.2@4571.26,495.24 4636.5,430 4870,430 v1(4910,470) ; v1(5730,595) 5735,595 5737.28,592.72 D8_CMCh4.1@5775.47,592.72
  Bottom Layer w6: v1(4910,470) 5035,595 v1(5730,595)
NetD11_NoCMCh1_1: D11_NoCMCh1.1 K2_NoCMCh1.2 | length 845
  Top Layer w6: v1(5240,1810) 5250,1800 5270,1800 5275,1795 K2_NoCMCh1.2@5275,1760.24 ; v1(5700,1560) 5772.76,1560 D11_NoCMCh1.1@5775.48,1557.28
  VDD w6: v1(5240,1810) 5250,1800 5680,1800 5700,1780 v1(5700,1560)
NetD11_NoCMCh2_1: D11_NoCMCh2.1 K2_NoCMCh2.2 | length 537.1
  Top Layer w6: K2_NoCMCh2.2@5275,1380.24 5275,1415 5279.49,1419.49 D11_NoCMCh2.1@5775.48,1419.49
NetD11_NoCMCh3_1: D11_NoCMCh3.1 K2_NoCMCh3.2 | length 724.2
  Top Layer w6: K2_NoCMCh3.2@5275,1010.24 5279.76,1015 v1(5300,1015) ; v1(5745,1280) 5773.78,1280 D11_NoCMCh3.1@5775.48,1281.69
  VDD w6: v1(5300,1015) 5345,1060 5675,1060 5695,1080 5695,1270 5705,1280 v1(5745,1280)
NetD11_NoCMCh4_1: D11_NoCMCh4.1 K2_NoCMCh4.2 | length 923.7
  Top Layer w6: K2_NoCMCh4.2@5275,640.24 5275,700 5287.87,712.87 5617.87,712.87 v1(5740,835) ; v1(5745,1145) 5774.38,1145 D11_NoCMCh4.1@5775.48,1143.9
  VDD w6: v1(5740,835) 5740,1140 v1(5745,1145)
NetJ2_15: J2.15 R5.1 | length 275.7
  Top Layer w6: R5.1@1258.7,1831.5 1342.2,1915 1415,1915 J2.15@1475,1975
NetJ2_16: J2.16 R6.1 | length 430.3
  Top Layer w6: R6.1@1198.7,1831.5 1198.7,1863.7 1210,1875 1275,1875 1333.61,1933.61 1392.14,1933.61 1416.39,1957.86 1416.39,2016.39 J2.16@1475,2075
NetJ2_17: J2.17 R7.1 | length 235.8
  Top Layer w6: R7.1@1398.68,1831.5 1454.44,1887.25 1465.4,1887.25 1553.15,1975 J2.17@1575,1975
NetJ2_18: J2.18 R8.1 | length 406.8
  Top Layer w6: R8.1@1338.68,1831.5 1338.68,1891.86 1347.95,1901.13 1459.65,1901.13 1516.39,1957.86 1516.39,2016.39 J2.18@1575,2075
NetJ2_27: J2.27 R9.1 | length 594.4
  Top Layer w6: R9.1@1540,1831.5 1631.51,1923.01 2023.01,1923.01 J2.27@2075,1975
NetJ2_28: J2.28 R10.1 | length 718.4
  Top Layer w6: R10.1@1480,1831.5 1582.12,1933.61 1592.14,1933.61 1620,1961.47 1620,2000 1645,2025 2025,2025 J2.28@2075,2075
NetJ2_29: J2.29 R11.1 | length 554.4
  Top Layer w6: R11.1@1680,1831.5 1743.76,1895.26 2095.26,1895.26 J2.29@2175,1975
NetJ2_30: J2.30 R12.1 | length 690.1
  Top Layer w6: R12.1@1620,1831.5 1697.64,1909.13 2067.66,1909.13 2125,1966.47 2125,2025 J2.30@2175,2075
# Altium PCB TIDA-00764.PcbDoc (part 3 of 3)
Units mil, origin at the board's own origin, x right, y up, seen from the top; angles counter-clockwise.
Board outline 6250 x 2150 mil, 4 copper layers (Top Layer, GND, VDD, Bottom Layer), stack 61.6 mil thick; 231 components, 137 nets, 687 pads, 247 vias.

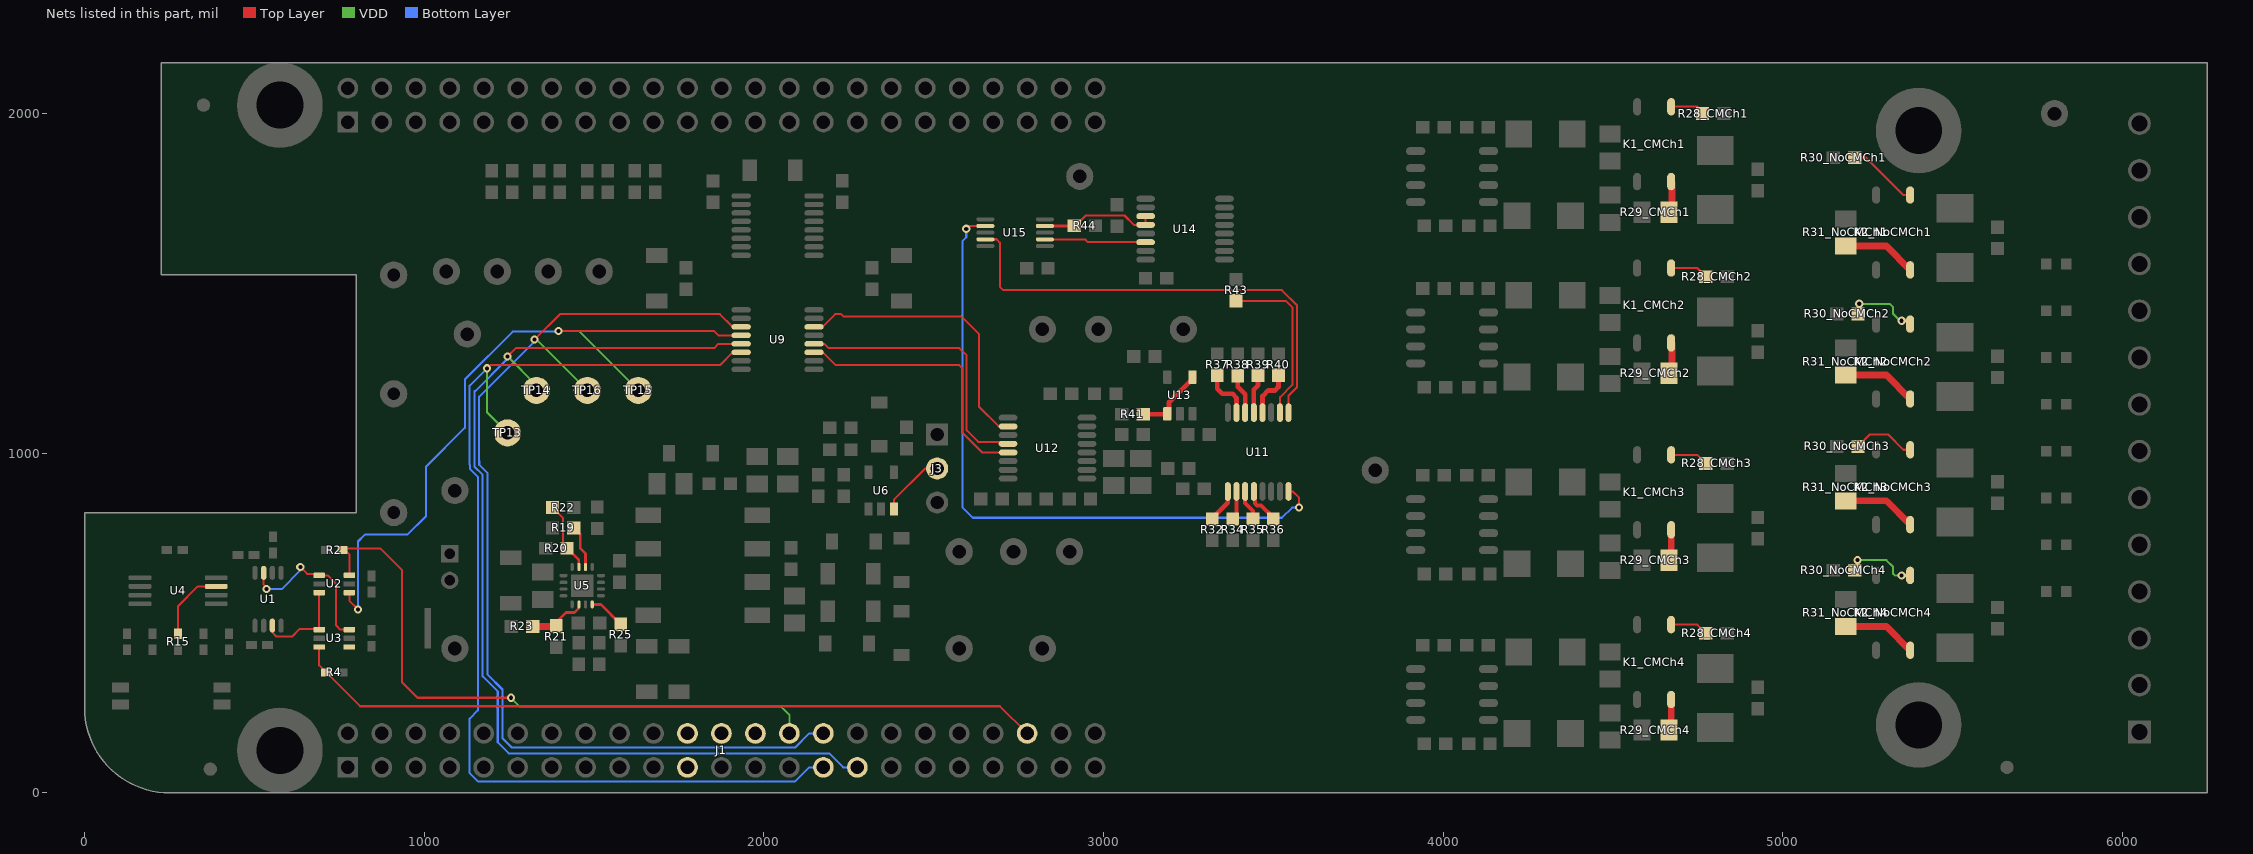
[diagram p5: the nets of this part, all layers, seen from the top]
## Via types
v1: diameter 24, hole 12, Top Layer to Bottom Layer, 201 vias
v2: diameter 39.37, hole 19.68, Top Layer to Bottom Layer, 24 vias
v3: diameter 32, hole 20, Top Layer to Bottom Layer, 17 vias
v4: diameter 19.68, hole 7.87, Top Layer to Bottom Layer, tented top, 5 vias

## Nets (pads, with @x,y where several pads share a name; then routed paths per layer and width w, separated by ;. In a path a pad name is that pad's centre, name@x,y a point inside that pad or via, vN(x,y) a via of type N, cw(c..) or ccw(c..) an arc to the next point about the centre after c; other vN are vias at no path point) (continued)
NetJ3_2: J3.2 U6.3 | length 193.9
  Top Layer w6: U6.3@2382.72,837.4 U6.3@2382.72,835.87 2382.72,862.72 2475,955 J3.2@2510,955
NetK1_CMCh1_1: K1_CMCh1.1 R28_CMCh1.1 | length 105.6
  Top Layer w6: K1_CMCh1.1@4671.26,2020.24 4748.27,2020.24 R28_CMCh1.1@4768.5,2000
NetK1_CMCh1_4: K1_CMCh1.4 R29_CMCh1.2 | length 93.9
  Top Layer w20: R29_CMCh1.2@4663.48,1706.99 4673.48,1716.99 K1_CMCh1.4@4673.48,1796.75
NetK1_CMCh2_1: K1_CMCh2.1 R28_CMCh2.1 | length 112.7
  Top Layer w6: K1_CMCh2.1@4671.26,1545.24 4748.27,1545.24 R28_CMCh2.1@4773.5,1520
NetK1_CMCh2_4: K1_CMCh2.4 R29_CMCh2.2 | length 93.9
  Top Layer w20: R29_CMCh2.2@4663.48,1233.72 4673.48,1243.72 K1_CMCh2.4@4673.48,1323.48
NetK1_CMCh3_1: K1_CMCh3.1 R28_CMCh3.1 | length 112.7
  Top Layer w6: K1_CMCh3.1@4671.26,995.24 4748.27,995.24 R28_CMCh3.1@4773.5,970
NetK1_CMCh3_4: K1_CMCh3.4 R29_CMCh3.2 | length 93.9
  Top Layer w20: R29_CMCh3.2@4661.26,685 4671.26,695 K1_CMCh3.4@4671.26,774.76
NetK1_CMCh4_1: K1_CMCh4.1 R28_CMCh4.1 | length 112.7
  Top Layer w6: K1_CMCh4.1@4671.26,495.24 4748.27,495.24 R28_CMCh4.1@4773.5,470
NetK1_CMCh4_4: K1_CMCh4.4 R29_CMCh4.2 | length 93.9
  Top Layer w20: R29_CMCh4.2@4661.26,185 4671.26,195 K1_CMCh4.4@4671.26,274.76
NetK2_NoCMCh1_1: K2_NoCMCh1.1 R30_NoCMCh1.1 | length 209
  Top Layer w6: R30_NoCMCh1.1@5211.5,1870 5245,1870 5354.76,1760.24 K2_NoCMCh1.1@5375,1760.24
NetK2_NoCMCh1_4: K2_NoCMCh1.4 R31_NoCMCh1.2 | length 219.1
  Top Layer w20: R31_NoCMCh1.2@5185,1610 5304.76,1610 K2_NoCMCh1.4@5375,1539.76
NetK2_NoCMCh2_1: K2_NoCMCh2.1 R30_NoCMCh2.1 | length 217.9
  Top Layer w6: R30_NoCMCh2.1@5221.5,1410 5221.5,1436.5 v1(5225,1440) ; v1(5350,1390) 5365.24,1390 K2_NoCMCh2.1@5375,1380.24
  VDD w6: v1(5225,1440) 5315,1440 5325,1430 5325,1410 5345,1390 v1(5350,1390)
NetK2_NoCMCh2_4: K2_NoCMCh2.4 R31_NoCMCh2.2 | length 219.1
  Top Layer w20: R31_NoCMCh2.2@5185,1230 5304.76,1230 K2_NoCMCh2.4@5375,1159.76
NetK2_NoCMCh3_1: K2_NoCMCh3.1 R30_NoCMCh3.1 | length 186.5
  Top Layer w6: R30_NoCMCh3.1@5221.5,1020 5256.5,1055 5310,1055 5354.76,1010.24 K2_NoCMCh3.1@5375,1010.24
NetK2_NoCMCh3_4: K2_NoCMCh3.4 R31_NoCMCh3.2 | length 219.1
  Top Layer w20: R31_NoCMCh3.2@5185,860 5304.76,860 K2_NoCMCh3.4@5375,789.76
NetK2_NoCMCh4_1: K2_NoCMCh4.1 R30_NoCMCh4.1 | length 219
  Top Layer w6: R30_NoCMCh4.1@5211.5,655 5220,663.5 v1(5220,685) ; v1(5350,640) 5374.76,640 K2_NoCMCh4.1@5375,640.24
  VDD w6: v1(5220,685) 5305,685 5325,665 5325,645 5330,640 v1(5350,640)
NetK2_NoCMCh4_4: K2_NoCMCh4.4 R31_NoCMCh4.2 | length 219.1
  Top Layer w20: R31_NoCMCh4.2@5185,490 5304.76,490 K2_NoCMCh4.4@5375,419.76
NetR15_2: R15.2 U4.3 | length 217.5
  Top Layer w6: R15.2@275.01,468.64 275.01,550.01 332.8,607.8 U4.3@387.2,607.8
NetR19_1: R19.1 U5.14 | length 129.1
  Top Layer w8: R19.1@1440.4,780 1458.9,761.5 1458.9,720.43 1474.84,704.49 U5.14@1474.84,665.12
NetR20_1: R20.1 R22.2 U5.15 | length 207.1
  Top Layer w6: R22.2@1377.4,840 1408.9,808.5 1408.9,731.5 R20.1@1420.4,720
  Top Layer w8: R20.1@1420.4,720 1455.16,685.24 U5.15@1455.16,665.12
NetR21_2: R21.2 R23.2 U5.6 | length 176.2
  Top Layer w8: R21.2@1388.9,491.5 1388.9,502.99 1417.11,531.2 1442.35,531.2 1455.16,544.01 U5.6@1455.16,554.88
  Top Layer w20: R23.2@1318.9,490 1387.4,490 R21.2@1388.9,491.5
NetR25_2: R25.2 U5.8 | length 108.3
  Top Layer w8: U5.8@1494.53,554.88 1519.96,554.88 R25.2@1578.55,496.3
NetR32_1: R32.1 U11.9 | length 102.7
  Top Layer w14: R32.1@3316.63,805.04 3365.75,854.15 U11.9@3365.75,887.4
NetR34_1: R34.1 U11.10 | length 85.6
  Top Layer w12: R34.1@3380,806.5 3391.34,817.83 U11.10@3391.34,887.4
NetR35_1: R35.1 U11.11 | length 90.5
  Top Layer w12: U11.11@3416.93,887.4 3416.93,853.07 3440,830 R35.1@3440,806.5
NetR36_1: R36.1 U11.12 | length 111.7
  Top Layer w12: U11.12@3442.52,887.4 3445.38,884.54 3445.38,852.73 3452.14,845.97 3464.03,845.97 3500,810 R36.1@3500,806.5
NetR37_1: R37.1 U11.7 | length 150.3
  Top Layer w14: R37.1@3335,1229.08 3335,1190 3350,1175 3380,1175 3391.34,1163.66 U11.7@3391.34,1119.68
NetR38_1: R38.1 U11.6 | length 118.5
  Top Layer w14: R38.1@3395,1229.08 3395,1195 3416.93,1173.07 U11.6@3416.93,1119.68
NetR39_1: R39.1 U11.5 | length 114.6
  Top Layer w14: U11.5@3442.52,1119.68 3442.52,1187.53 3455,1200.01 R39.1@3455,1229.08
NetR40_1: R40.1 U11.4 | length 140.5
  Top Layer w14: U11.4@3468.11,1119.68 3468.11,1168.11 3485,1185 3505,1185 3515,1195 R40.1@3515,1229.08
NetR41_2: R41.2 U13.1 U13.4 | length 215.7
  Top Layer w14: R41.2@3116.5,1115 3191.73,1115 3192.6,1115.87 3192.6,1149.33 U13.4@3267.4,1224.13
NetR43_1: R43.1 U11.2 | length 498.9
  Top Layer w6: R43.1@3390,1448.5 3536.88,1448.5 3556.13,1429.25 3556.13,1201.13 3520,1165 3520,1120.39 U11.2@3519.29,1119.68
NetR44_1: R44.1 U14.11 U14.12 U15.9 | length 346.4
  Top Layer w6: R44.1@2908.19,1669.68 2917.42,1669.68 2947.73,1700 3061.64,1700 3089.16,1672.48 U14.12@3123.86,1672.48 U14.11@3123.86,1698.07
  Top Layer w10: U15.9@2827.28,1669.06 2907.56,1669.06 R44.1@2908.19,1669.68
NetU1_3: U1.3 U2.3 U3.1 | length 282.2
  Top Layer w6: U1.3@552.8,492.37 552.8,472.33 565,460.13 610.58,460.13 633.45,483 688.46,483 690.72,480.73 U2.3@690.72,589.52
NetU1_7: U1.7 U2.1 U3.6 | length 478.7
  Top Layer w6: U1.7@527.2,647.76 527.2,612.8 535,605 v1(535,600) ; v1(635,665) 655.13,644.87 690.71,644.87 U2.1@690.71,640.59 715.49,640.61 740.02,616.08 740.02,493.62 753.03,480.61 U3.6@779.31,480.61
  Bottom Layer w6: v1(535,600) 579.98,600 635,655.01 v1(635,665)
NetU11_1: U11.1 U15.4 | length 1400.9
  Top Layer w6: U15.4@2652.09,1629.68 2652.09,1630 2685,1630 2695,1620 2695,1490 2705,1480 3525,1480 3570,1435 3570,1195 3544.88,1169.88 U11.1@3544.88,1119.68
NetU11_16: U11.16 U15.2 | length 1972.2
  Top Layer w6: v1(2595.75,1660.75) 2604.06,1669.06 U15.2@2652.09,1669.06 ; U11.16@3544.88,887.4 3557.6,887.4 3575,870 v1(3575,840)
  Bottom Layer w6: v1(2595.75,1660.75) 2595.75,1635.75 2585,1625 2585,840 2615,810 3525,810 3555,840 v1(3575,840) v1@3580,840
NetU14_14: U14.14 U15.7 | length 300
  Top Layer w6: U15.7@2827.28,1629.68 2945.32,1629.68 2953.7,1621.3 U14.14@3123.86,1621.3
SCLK_ISO: U9.12 U12.12 | length 822.2
  Top Layer w6: U9.12@2147.6,1322.07 2177.93,1322.07 2190.43,1309.57 2227.32,1309.57 2575.43,1309.57 2597.13,1287.87 2597.13,1067.49 2630.97,1033.65 2713,1033.65 U12.12@2718.86,1027.8
SDI_ISO: U9.14 U12.10 | length 849.2
  Top Layer w6: U9.14@2147.6,1372.07 2152.98,1372.07 2154.78,1373.87 2174.31,1373.87 2210,1409.57 2227.32,1409.57 2234.77,1402.13 2582.13,1402.13 2633.87,1350.38 2633.87,1136.13 2691.02,1078.98 U12.10@2718.86,1078.98
SDO1_ISO: U9.11 U12.13 | length 813
  Top Layer w6: U9.11@2147.6,1297.07 2173.48,1297.07 2210.98,1259.57 2227.32,1259.57 2575.43,1259.57 2583.25,1251.75 2583.25,1061.75 2642.8,1002.2 U12.13@2718.86,1002.2 U12.13@2713,1008.06
SPI_A: J1.28 R2.2 U2.6 | length 1834.5
  Top Layer w6: R2.2@766.51,715.01 779.31,702.22 U2.6@779.29,640.59 ; R2.2@771.51,720.01 869.98,720.01 935,655 935,325 980,280 v1(1255,280)
  VDD w6: v1(1255,280) 1280,255 2050,255 2075,230 J1.28@2075,175
SPI_B: J1.42 R4.2 U3.3 | length 2228.2
  Top Layer w6: U3.3@695.72,424.42 U3.3@690.72,429.42 690.72,375.65 R4.2@711.38,355 811.38,255 2695,255 J1.42@2775,175
SPI_CLK: J1.31 TP14.1 U9.5 | length 3134.4
  Top Layer w6: v1(1245,1285) 1269.57,1309.57 1853.31,1309.57 1865.81,1322.07 U9.5@1933.03,1322.07
  VDD w6: v1(1245,1285) 1330,1200 TP14.1@1330,1185
  Bottom Layer w6: v1(1245,1285) 1245,1277.65 1149.84,1182.49 1147.49,1182.49 1147.49,971.95 1147.95,971.49 1147.95,960 1171.73,936.22 1171.73,343.27 1216.39,298.61 1216.39,148.61 1248.61,116.39 2192.14,116.39 2233.53,75 J1.31@2275,75
SPI_CSA: TP15.1 U2.4 U9.4 | length 2126.1
  Top Layer w6: U2.4@779.29,589.41 779.29,565.71 v1(805,540) ; v1(1395,1360) 1852.88,1360 1853.31,1359.57 1865.81,1347.07 U9.4@1933.03,1347.07
  VDD w6: v1(1395,1360) 1455,1360 TP15.1@1630,1185
  Bottom Layer w6: v1(805,540) 805,740 825,760 950,760 1005,815 1005,960 1119.74,1074.74 1119.74,1217.09 1260.53,1357.87 1392.87,1357.87 v1(1395,1360)
SPI_CSB: U3.4
SPI_MISO: J1.29 TP13.1 U9.6 | length 3284.5
  Top Layer w6: v1(1185,1250) 1194.57,1259.57 1853.31,1259.57 1870.71,1259.57 1908.21,1297.07 U9.6@1933.03,1297.07
  VDD w6: v1(1185,1250) 1185,1120 TP13.1@1245,1060
  Bottom Layer w6: v1(1185,1250) 1133.61,1198.61 1133.61,966.21 1134.07,965.75 1134.07,954.25 1157.86,930.47 1157.86,242.86 1133.61,218.61 1133.61,57.86 1157.86,33.61 2092.14,33.61 2133.53,75 J1.29@2175,75
SPI_MOSI: J1.30 TP16.1 U9.3 | length 3115
  Top Layer w6: v1(1325,1335) 1399.57,1409.57 1853.31,1409.57 1870,1409.57 1907.5,1372.07 U9.3@1933.03,1372.07
  VDD w6: v1(1325,1335) 1330,1335 TP16.1@1480,1185
  Bottom Layer w6: v1(1325,1335) 1325,1330 1161.36,1166.36 1161.36,977.7 1161.82,977.24 1161.82,965.75 1185.61,941.96 1185.61,349.02 1230.26,304.36 1230.26,161.21 1257.86,133.61 2092.14,133.61 2133.53,175 J1.30@2175,175
UART_RXD1: J1.26
UART_RXD2: J1.22
UART_TXD1: J1.24
UART_TXD2: J1.21
pads on no net: FID1.1 FID2.1 FID3.1 J1.9 J1.10 J1.11 J1.12 J1.13 J1.14 J1.15 J1.16 J1.17 J1.18 J1.23 J1.25 J1.27 J1.32 J1.33 J1.34 J1.35 J1.36 J1.37 J1.38 J1.39 J1.40 J1.41 J2.3 J2.4 J2.5 J2.6 J2.7 J2.8 J2.9 J2.10 J2.13 J2.14 J2.19 J2.20 J2.21 J2.22 J2.23 J2.24 J2.25 J2.26 J2.31 J2.32 J2.33 J2.34 J2.35 J2.36 J2.37 J2.38 J2.39 J2.40 J2.41 J2.42 J2.43 J2.44 J2.45 J2.46 MH1.1 MH2.1 MH3.1 MH4.1 SH-J1.0 T1.3 U7_CMCh1.8 U7_CMCh2.8 U7_CMCh3.8 U7_CMCh4.8 U10.7 U12.14 U12.15 U14.9
copper on no net: | length 103920.8
  Top Layer w1: 10399.86,6070.32 10499.54,6170 10619.54,6290 10739.54,6410 10859.54,6530 10979.54,6650 11099.54,6770 11219.54,6890 11339.54,7010 11459.54,7130 11519.54,7190 ; 10399.86,6130.32 10439.54,6170 10559.54,6290 10679.54,6410 10799.54,6530 10919.54,6650 11039.54,6770 11159.54,6890 11279.54,7010 11399.54,7130 11519.54,7250 ; 10399.86,6190.32 10499.54,6290 10619.54,6410 10739.54,6530 10859.54,6650 10979.54,6770 11099.54,6890 11219.54,7010 11339.54,7130 11459.54,7250 11519.54,7310 ; 10399.86,6250.32 10439.54,6290 10559.54,6410 10679.54,6530 10799.54,6650 10919.54,6770 11039.54,6890 11159.54,7010 11279.54,7130 11399.54,7250 11519.54,7370 ; 10399.86,6310.32 10499.54,6410 10619.54,6530 10739.54,6650 10859.54,6770 10979.54,6890 11099.54,7010 11219.54,7130 11339.54,7250 11459.54,7370 ; 10399.86,6370.32 10439.54,6410 10559.54,6530 10679.54,6650 10799.54,6770 10919.54,6890 11039.54,7010 11159.54,7130 11279.54,7250 11399.54,7370 ; 10399.86,6430.32 10499.54,6530 10619.54,6650 10739.54,6770 10859.54,6890 10979.54,7010 11099.54,7130 11219.54,7250 11339.54,7370 ; 10399.86,6490.32 10439.54,6530 10559.54,6650 10679.54,6770 10799.54,6890 10919.54,7010 11039.54,7130 11159.54,7250 11279.54,7370 ; 10399.86,6550.32 10499.54,6650 10619.54,6770 10739.54,6890 10859.54,7010 10979.54,7130 11099.54,7250 11219.54,7370 ; 10399.86,6610.32 10439.54,6650 10559.54,6770 10679.54,6890 10799.54,7010 10919.54,7130 11039.54,7250 11159.54,7370 ; 10399.86,6670.32 10499.54,6770 10619.54,6890 10739.54,7010 10859.54,7130 10979.54,7250 11099.54,7370 ; 10399.86,6730.32 10439.54,6770 10559.54,6890 10679.54,7010 10799.54,7130 10919.54,7250 11039.54,7370 ; 10399.86,6790.32 10499.54,6890 10619.54,7010 10739.54,7130 10859.54,7250 10979.54,7370 ; 10399.86,6850.32 10439.54,6890 10559.54,7010 10679.54,7130 10799.54,7250 10919.54,7370 ; 10399.86,6910.32 10499.54,7010 10619.54,7130 10739.54,7250 10859.54,7370 ; 10399.86,6970.32 10439.54,7010 10559.54,7130 10679.54,7250 10799.54,7370 ; 10399.86,7030.32 10499.54,7130 10619.54,7250 10739.54,7370 ; 10399.86,7090.32 10439.54,7130 10559.54,7250 10679.54,7370 ; 10399.86,7150.32 10499.54,7250 10619.54,7370 ; 10399.86,7210.32 10439.54,7250 10559.54,7370 ; 10399.86,7270.32 10499.54,7370 ; 10399.86,7330.32 10439.54,7370 ; 10439.54,6050 10559.54,6170 10679.54,6290 10799.54,6410 10919.54,6530 11039.54,6650 11159.54,6770 11279.54,6890 11399.54,7010 11519.54,7130 ; 10499.54,6050 10619.54,6170 10739.54,6290 10859.54,6410 10979.54,6530 11099.54,6650 11219.54,6770 11339.54,6890 11459.54,7010 11519.54,7070 ; 10559.54,6050 10679.54,6170 10799.54,6290 10919.54,6410 11039.54,6530 11159.54,6650 11279.54,6770 11399.54,6890 11519.54,7010 ; 10619.54,6050 10739.54,6170 10859.54,6290 10979.54,6410 11099.54,6530 11219.54,6650 11339.54,6770 11459.54,6890 11519.54,6950 ; 10679.54,6050 10799.54,6170 10919.54,6290 11039.54,6410 11159.54,6530 11279.54,6650 11399.54,6770 11519.54,6890 ; 10739.54,6050 10859.54,6170 10979.54,6290 11099.54,6410 11219.54,6530 11339.54,6650 11459.54,6770 11519.54,6830 ; 10799.54,6050 10919.54,6170 11039.54,6290 11159.54,6410 11279.54,6530 11399.54,6650 11519.54,6770 ; 10859.54,6050 10979.54,6170 11099.54,6290 11219.54,6410 11339.54,6530 11459.54,6650 11519.54,6710 ; 10919.54,6050 11039.54,6170 11159.54,6290 11279.54,6410 11399.54,6530 11519.54,6650 ; 10979.54,6050 11099.54,6170 11219.54,6290 11339.54,6410 11459.54,6530 11519.54,6590 ; 11039.54,6050 11159.54,6170 11279.54,6290 11399.54,6410 11519.54,6530 ; 11099.54,6050 11219.54,6170 11339.54,6290 11459.54,6410 11519.54,6470 ; 11159.54,6050 11279.54,6170 11399.54,6290 11519.54,6410 ; 11219.54,6050 11339.54,6170 11459.54,6290 11519.54,6350 ; 11279.54,6050 11399.54,6170 11519.54,6290 ; 11339.54,6050 11459.54,6170 11519.54,6230 ; 11399.54,6050 11519.54,6170 ; 11459.54,6050 11519.54,6110
  Top Layer w15: 6980.74,6170 7390.65,6170 8320.4,6170 9180.16,6170 9830,6170 10399.86,6170 11519.54,6170 ; 6980.74,6290 7390.65,6290 8320.4,6290 9180.16,6290 9830,6290 10399.86,6290 11519.54,6290 ; 6980.74,6410 7390.65,6410 8320.4,6410 9180.16,6410 9830,6410 10399.86,6410 11519.54,6410 ; 6980.74,6530 7390.65,6530 8320.4,6530 9180.16,6530 9830,6530 10399.86,6530 11519.54,6530 ; 6980.74,6650 7390.65,6650 8320.4,6650 9180.16,6650 9830,6650 10399.86,6650 11519.54,6650 ; 6980.74,6770 7390.65,6770 8320.4,6770 9180.16,6770 9830,6770 10399.86,6770 11519.54,6770 ; 6980.74,6890 7390.65,6890 8320.4,6890 9180.16,6890 9830,6890 10399.86,6890 11519.54,6890 ; 6980.74,7010 7390.65,7010 8320.4,7010 9180.16,7010 9830,7010 10399.86,7010 11519.54,7010 ; 6980.74,7130 7390.65,7130 8320.4,7130 9180.16,7130 9830,7130 10399.86,7130 11519.54,7130 ; 6980.74,7250 7390.65,7250 8320.4,7250 9180.16,7250 9830,7250 10399.86,7250 11519.54,7250 ; 6980.74,7370 11519.54,7370 ; 7390.65,7490 7390.65,6050 ; 8320.4,7490 8320.4,6050 ; 9180.16,7490 9180.16,6050 ; 9830,7490 9830,6050 ; 10399.86,7490 10399.86,6050 ; 7390.65,6050 6980.74,6050 6980.74,7490 11519.54,7490 11519.54,6050 10399.86,6050 ; 7390.65,6050 8320.4,6050 ; 8320.4,6050 9180.16,6050 ; 9180.16,6050 9830,6050 ; 9830,6050 10399.86,6050
  other v2: 575,27.56 490.61,76.28 659.39,76.28 5400,102.56 5315.61,151.28 5484.39,151.28 490.61,173.72 659.39,173.72 575,222.44 5315.61,248.72 5484.39,248.72 5400,297.44 5400,1852.56 5315.61,1901.28 5484.39,1901.28 575,1927.56 490.61,1976.28 659.39,1976.28 5315.61,1998.72 5484.39,1998.72 5400,2047.44 490.61,2073.72 659.39,2073.72 575,2122.44

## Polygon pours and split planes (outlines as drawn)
DGND on GND "DGND" (solid, pour order 39): 0,250 0,825 800,825 800,1525 225,1525 225,2150 2025,2150 3100,2150 3100,1900 2025,1900 2025,1075 1605,1075 1605,700 1800,700 1800,250 3100,250 3100,0 1825,0 250,0 cw(c250,250)
GND_ISO on GND "GND_ISO_L02_P045" (solid, remove dead copper, pour order 45): 2025,2150 2025,1075 1605,1075 1605,690 1825,690 1825,0 6255,0 6255,2150
+15V_ISO on VDD "+15V_ISO_L03_P053" (solid, remove dead copper, pour order 53): 2216.52,555 2216.52,480 4051.52,480 4051.52,81.71 4100,81.71 4100,1671.71 4051.52,1671.71 4051.52,555
-15V_ISO on VDD "-15V_ISO_L03_P051" (solid, remove dead copper, pour order 51): 2265,660 2265,580 4025,580 4025,2025 3975,2025 3975,660
DVDD on VDD "+5V" (solid, pour order 47): 0,250 0,825 830,825 830,1650 980,1650 980,250 3100,250 3100,0 990,0 250,0 cw(c250,250)
+5V on VDD "+5V_L03_P065" (solid, remove dead copper, pour order 65): 1150,300 1030,420 1030,1900 2000,1900 2000,1100 1580,1100 1580,700 1800,700 1800,300
+5V_ISO on VDD "+5V_ISO_L03_P049" (solid, pour order 49): 1615,750 2670,750 2735,770 2800,750 3100,750 ccw(c3100,800) 3150,800 3150,1400 cw(c3200,1400) 3200,1450 3400,1450 ccw(c3400,1500) 3450,1500 3450,1825 ccw(c3400,1825) 3400,1875 2025,1875 2025,1070 1615,1070
NetC10_1 on Top Layer "NETC10_1_L01_P077" (solid, remove dead copper, pour order 77): 1508.88,645 1535,645 1540,640 1695,640 1695,600 1540,600 1535,595 1508.75,595
-15V_ISO on Top Layer "-15V_ISO_L01_P075" (solid, pour order 75): 2295,765 2295,580 2475,580 2495,600 2495,640 2475,660 2350,660 2350,765
+15V_ISO on Top Layer "+15V_ISO_L01_P073" (solid, pour order 73): 2285,570 2285,465 2285,410 2330,410 2330,475 2485,475 2495,485 2495,540 2475,560 2345,560 2345,570
DGND on Top Layer "DGND_L01_P059" (solid, pour order 59): 1444.87,606.38 1299.87,606.38 1289.87,596.38 1219.87,596.38 1219.87,551.38 1439.87,551.38 1439.87,571.38 1444.87,576.38 1454.87,576.38 1454.87,596.38
+15V_ISO on Top Layer "+15V_ISO_L01_P067" (solid, pour order 67): 3200,540.25 3235.02,565.02 3254.62,565.02 3290,540 3290,520 3290,510.04 3200,510.04
+5V on Top Layer "+5V_L01_P057" (solid, pour order 57): 1308.9,625 1383.9,625 1393.9,615 1403.9,615 1413.9,615 1418.9,620 1418.9,650 1423.9,655 1438.9,655 1438.9,675 1433.9,680 1423.9,690 1393.9,690 1388.9,695 1388.9,795 1333.9,795 1328.9,790 1328.9,715 1323.9,710 1223.9,710
-15V_ISO on Top Layer "-15V_ISO_L01_P069" (solid, pour order 69): 3100,630 3178.89,706.11 3195,690 3195,615 3105,615
DGND on Bottom Layer "DGND_L04_P071" (solid, pour order 71): 1180,420 1330,270 1765,270 1800,305 1800,700 1580,700 1580,880 1555,905 1205,905 1180,880

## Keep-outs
Keep-Out Layer:
  lines w10: 800,825 0,825 0,250 ccw(c250,250) 250,0 6250,0 6250,2150 225,2150 225,1525 800,1525 800,825 ; 800,825 800,825
  text ".Layer_Name" at 577,-858.49 h60

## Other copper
Top Layer:
  text "Layer" at 7040.74,7400 h60
  text "Name" at 7450.65,7400 h60
  text "Material" at 8380.4,7400 h60
  text "Thickness" at 9240.16,7400 h60
  text "Constant" at 9890,7400 h60
  text "Board Layer Stack" at 10459.86,7400 h60
  text "1" at 7040.74,7280 h60
  text "Top Overlay" at 7450.65,7280 h60
  text "2" at 7040.74,7160 h60
  text "Top Solder" at 7450.65,7160 h60
  text "Solder Resist" at 8380.4,7160 h60
  text "0,40mil" at 9240.16,7160 h60
  text "3,5" at 9890,7160 h60
  text "3" at 7040.74,7040 h60
  text "Top Layer" at 7450.65,7040 h60
  text "Copper" at 8380.4,7040 h60
  text "1,40mil" at 9240.16,7040 h60
  text "4" at 7040.74,6920 h60
  text "Dielectric 1" at 7450.65,6920 h60
  text "8,00mil" at 9240.16,6920 h60
  text "4,2" at 9890,6920 h60
  text "5" at 7040.74,6800 h60
  text "GND" at 7450.65,6800 h60
  text "Copper" at 8380.4,6800 h60
  text "1,40mil" at 9240.16,6800 h60
  text "6" at 7040.74,6680 h60
  text "Dielectric 2" at 7450.65,6680 h60
  text "FR-4" at 8380.4,6680 h60
  text "40,00mil" at 9240.16,6680 h60
  text "4,2" at 9890,6680 h60
  text "7" at 7040.74,6560 h60
  text "VDD" at 7450.65,6560 h60
  text "Copper" at 8380.4,6560 h60
  text "1,40mil" at 9240.16,6560 h60
  text "8" at 7040.74,6440 h60
  text "Dielectric 3" at 7450.65,6440 h60
  text "8,00mil" at 9240.16,6440 h60
  text "4,2" at 9890,6440 h60
  text "9" at 7040.74,6320 h60
  text "Bottom Layer" at 7450.65,6320 h60
  text "Copper" at 8380.4,6320 h60
  text "1,40mil" at 9240.16,6320 h60
  text "10" at 7040.74,6200 h60
  text "Bottom Solder" at 7450.65,6200 h60
  text "Solder Resist" at 8380.4,6200 h60
  text "0,40mil" at 9240.16,6200 h60
  text "3,5" at 9890,6200 h60
  text "11" at 7040.74,6080 h60
  text "Bottom Overlay" at 7450.65,6080 h60
  text ".Layer_Name" at 577,-858.49 h60
GND:
  pour cut-out: 3100,2150 3150,2150 3150,1900 3100,1900
  pour cut-out: 2000,1875 2000,1925 3150,1925 3150,1875
  pour cut-out: 1800,250 1800,300 3150,300 3150,250
  pour cut-out: 3100,300 3150,300 3150,0 3100,0
  pour cut-out: 2000,1924 2050,1924 2050,1050 2000,1050
  pour cut-out: 1800,750 1850,750 1850,250 1800,250
  pour cut-out: 2050,1100 2050,1050 1580,1050 1580,1100
  pour cut-out: 1630,700 1580,700 1580,1100 1630,1100
  pour cut-out: 1580,700 1580,750 1849.85,750 1849.85,700
VDD:
  pour cut-out: 3100,2150 3150,2150 3150,1900 3100,1900
  pour cut-out: 2000,1875 2000,1925 3150,1925 3150,1875
  pour cut-out: 3100,300 3150,300 3150,0 3100,0
  pour cut-out: 1800,250 1800,300 3150,300 3150,250
  pour cut-out: 2000,1923.44 2050,1923.44 2050,1050 2000,1050
  pour cut-out: 2050,1100 2050,1050 1580,1050 1580,1100
  pour cut-out: 1630,700 1580,700 1580,1100 1630,1100
  pour cut-out: 1580,700 1580,750 1849.85,750 1849.85,700
  pour cut-out: 1800,750 1850,750 1850,250 1800,250
Bottom Layer:
  text ".Layer_Name" at 577,-858.49 h60

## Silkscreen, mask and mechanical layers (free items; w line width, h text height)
Top Overlay:
  rectangle: 3455,50 3755,130
  text "_RCLK" at 2715,1805 h30
  text "CMCh1" at 4195,1785 h80
  text "NoCMCh1" at 5260,1440 h80
  text "IN1+2" at 1000,1435 h30
  text "A0" at 1190,1435 h30
  text "A1" at 1345,1435 h30
  text "A2" at 1490,1435 h30
  text "ADC_in" at 2905,1435 h30
  text "MUX_out" at 3125,1435 h30
  text "GND" at 870,1430 h30
  text "CMCh2" at 4195,1320 h80
  text "CLK" at 1320,1085 h30
  text "CS" at 1585,1085 h30
  text "VDD" at 870,1075 h30
  text "MOSI" at 1440,1075 h30
  text "NoCMCh2" at 5260,1060 h80
  text "off" at 2585,1020 h72.83
  text "5V" at 2585,965 h60
  text "MISO" at 1200,955 h30
  text "on" at 2585,915 h72.83
  text "+5V" at 1165,870 h30
  text "CMCh3" at 4195,775 h80
  text "GND" at 870,735 h30
  text "NoCMCh3" at 5260,690 h80
  text "AVDD" at 2975,660 h30
  text "-15V_iso" at 2580,570 h30
  text "+5V_iso" at 2825,570 h30
  text "CAPE-ID AND" at 945,320 h30 r90
  text "ADDR-DEC" at 990,320 h30 r90
  text "+15V_iso" at 2645,315 h30
  text "NoCMCh4" at 5535,295 h80
  text "CMCh4" at 4195,270 h80
  text "TIDA-00764" at 3185,170 h60
  text "Version:" at 3185,65 h80
  text ".Layer_Name" at 577,-858.49 h30
Bottom Overlay:
  text ".Layer_Name" at 577,-858.49 h60
Top Paste:
  text ".Layer_Name" at 577,-858.49 h60
Bottom Paste:
  text ".Layer_Name" at 577,-858.49 h60
Top Solder:
  text ".Layer_Name" at 577,-858.49 h60
  text ".Layer_Name" at 577,-858.49 h60
Bottom Solder:
  text ".Layer_Name" at 577,-858.49 h60
Drill Guide:
  text ".Layer_Name" at 577,-858.49 h60
M1 Board Outline:
  the board outline again, w10
  text ".Layer_Name" at 577,-858.49 h60
M2 Board Dimensions:
  lines w10: 5.01,-154.98 5.01,-134.98 ; 65.01,-164.98 5.01,-144.98 ; 65.01,-124.98 5.01,-144.98 ; 2849.1,-144.98 5.01,-144.98 ; 3410.93,-144.98 6255.02,-144.98 ; 5083,651 5283,651 ; 6195.02,-164.98 6255.02,-144.98 ; 6195.02,-124.98 6255.02,-144.98 ; 6255.02,-194.98 6255.02,5.02 ; 6255.02,-154.98 6255.02,-134.98 ; 6385.02,65.02 6405.02,5.02 ; 6385.02,2095.01 6405.02,2155.01 ; 6395.02,5.02 6415.02,5.02 ; 6395.02,2155.01 6415.02,2155.01 ; 6405.02,804.1 6405.02,5.02 ; 6405.02,1355.93 6405.02,2155.01 ; 6425.02,65.02 6405.02,5.02 ; 6425.02,2095.01 6405.02,2155.01
  text "2150 (mil)" at 6441.01,814.1 h60 r90
  text "6250 (mil)" at 2859.1,-180.98 h60
  text ".Layer_Name" at 577,-858.49 h60
M3 3D STEP Top:
  text ".Layer_Name" at 577,-858.49 h60
M4 3D STEP Bottom:
  text ".Layer_Name" at 577,-858.49 h60
M5 Assembly Top:
  text "COMPONENTS MARKED 'DNP' SHOULD NOT BE POPULATED." at 1153.5,-318.5 h60
  text "ASSEMBLY VARIANT:" at 1153,-434 h60
  text ".VariantName" at 2189,-434 h60
  text "PCB VIEWED FROM TOP SIDE" at -228.5,-655.67 h60
  text "BOARD #:" at 2248,-655.67 h60
  text ".PRJ_Number" at 2793.5,-655.67 h60
  text "REV:" at 3638,-655.67 h60
  text ".PCB_Rev" at 3929.5,-655.67 h60
  text "SVN REV:" at 4476,-655.67 h60
  text ".VersionControl_RevNumber" at 4982,-655.67 h60
  text "TID #:" at 2248,-859 h60
  text ".TID" at 2793.5,-859 h60
  text "PLOT NAME =" at -228.5,-1064.34 h60
  text ".plot_File_Name" at 577,-1064.34 h60
  text "GENERATED    :" at 2250,-1064.34 h60
  text ".Print_Date" at 3119.5,-1064.34 h60
  text ".Print_Time" at 3848.5,-1064.34 h60
  text "TEXAS INSTRUMENTS" at 5113,-1064.34 h60
M6 Assembly Bottom:
  text "COMPONENTS MARKED 'DNP' SHOULD NOT BE POPULATED." at 6102,-318 h60
  text ".VariantName" at 5058,-434 h60
  text "ASSEMBLY VARIANT:" at 6097,-434 h60
  text ".VersionControl_RevNumber" at 1035.5,-656.17 h60
  text "SVN REV:" at 1541.5,-656.17 h60
  text ".PCB_Rev" at 2088,-656.17 h60
  text "REV:" at 2379.5,-656.17 h60
  text ".PRJ_Number" at 3224,-656.17 h60
  text "BOARD #:" at 3769.5,-656.17 h60
  text "PCB VIEWED FROM BOTTOM SIDE" at 6246,-656.17 h60
  text ".TID" at 3224,-859.5 h60
  text "TID #:" at 3769.5,-859.5 h60
  text "TEXAS INSTRUMENTS" at 904.5,-1064.84 h60
  text ".Print_Time" at 2169,-1064.84 h60
  text ".Print_Date" at 2898,-1064.84 h60
  text "GENERATED    :" at 3767.5,-1064.84 h60
  text ".plot_File_Name" at 5440.5,-1064.84 h60
  text "PLOT NAME =" at 6246,-1064.84 h60
M9 Title Sheet:
  drawing of 18 lines, arcs and shapes, not listed
  text "1" at 739.84,8036.5 h70
  text "2" at 3235.5,8036.5 h70
  text "3" at 5724.84,8036.5 h70
  text "4" at 8231.51,8036.5 h70
  text "5" at 10730.5,8036.5 h70
  text "6" at 13235.5,8036.5 h70
  text "A" at -416.5,6893.5 h70
  text "A" at 14383.5,6893.5 h70
  text "B" at -416.5,4513.5 h70
  text "B" at 14383.5,4513.5 h70
  text "C" at -416.5,2138.5 h70
  text "C" at 14383.5,2138.5 h70
  text "PROJECT TITLE:" at 11343.5,277.5 h45
  text ".PRJ_Title" at 11393.5,144.17 h70
  text "DESIGNED FOR:" at 11343.5,-23.5 h45
  text ".PRJ_Customer" at 11393.5,-163.5 h70
  text "D" at -416.5,-231.5 h70
  text "D" at 14383.5,-231.5 h70
  text "FILE NAME:" at 11343.5,-323.5 h45
  text ".PCB_File_Name_No_Path" at 11393.5,-443.5 h70
  text "Texas Instruments (TI) and/or its licensors do not warrant the accuracy or completeness of this specification" at 6374,-605.34 h45
  text "ENGINEER:" at 11343.5,-613.5 h45
  text "LAYOUT BY:" at 12848.5,-613.5 h45
  text "or any information contained therein. TI and/or its licensors do not warrant that this design will meet" at 6329.01,-718 h45
  text ".PRJ_Engineer" at 11393.5,-768.49 h70
  text ".PCB_Layout" at 12899,-768.49 h70
  text "the specifications, will be suitable for your application or fit for any particular purpose, or will operate in" at 6329.01,-830.67 h45
  text ".Layer_Name" at 577,-858.49 h60
  text "ALTIUM DESIGNER VERSION:" at 12848.5,-923.5 h45
  text "an implementation. TI and/or its licensors do not warrant that the design is production worthy. You should" at 6329.01,-943.33 h45
  text "completely validate and test your design implementation to confirm the system functionality for your application." at 6374,-1056 h45
  text ".print_Scale" at 11393.5,-1056.83 h70
  text ".Application_BuildNumber" at 12899,-1056.83 h70
  text "1" at 739.84,-1263.5 h70
  text "2" at 3235.5,-1263.5 h70
  text "3" at 5724.84,-1263.5 h70
  text "4" at 8231.51,-1263.5 h70
  text "5" at 10730.5,-1263.5 h70
  text "6" at 13235.5,-1263.5 h70
M10 Fab Notes:
  text "DESIGN INFORMATION" at 12381.02,5910 h60
  text "MIN. TRACK WIDTH:" at 11736.46,5730 h60
  text "8" at 12832.7,5730 h60
  text "MIL" at 12987.46,5730 h60
  text "MIN. CLEARANCE:" at 11736.46,5598 h60
  text "0.2" at 12772.7,5598 h60
  text "mm" at 12987.46,5598 h60
  text "MIN. VIA PAD SIZE:" at 11736.46,5466 h60
  text "24" at 12802.71,5466 h60
  text "MIL" at 12987.46,5466 h60
  text "0.05mm (2MIL)" at 12431.46,5324.29 h60
  text "MINIMUM ANNULAR RING" at 11407.23,5320 h60
  text "EXTERNAL" at 13139.46,5320 h60
  text "PER" at 11607.23,5202 h60
  text "IPC-D-275 CLASS 2 LEVEL C" at 11827.23,5202 h60
  text "MIL, HOLES" at 13315.46,5089.71 h60
  text "+/-" at 12923,5089 h60
  text "+/-" at 13777,5089 h60
  text "REGISTRATION TOLERANCES:" at 11407.23,5084 h60
  text "METAL" at 12607,5084 h60
  text "5" at 13183.2,5084 h60
  text "3" at 14016.2,5084 h60
  text "MIL" at 14132.46,5084 h60
  text "MATERIAL:" at 11332.46,4874.54 h60
  text "FR-4 High Tg" at 12318.9,4734.21 h60
  text "FR-408" at 11753.46,4725.64 h60
  text "X" at 12165.46,4725.64 h60
  text "OTHER" at 13241.46,4725.64 h60
  text "62 MIL (1.6mm) +/-10%" at 12073.56,4562.92 h60
  text "THICKNESS:" at 11407.23,4558.64 h60
  text "X" at 11945.4,4558.64 h60
  text "OTHER" at 13358.46,4558.64 h60
  text "TOLERANCE:" at 11407.23,4400.64 h60
  text "X" at 12246.53,4400.64 h60
  text "ANSI IPC-6012 TYPE 3 CLASS 2" at 12433.48,4400.64 h60
  text "OTHER +/-" at 12433.46,4244.64 h60
  text "BOW & TWIST:" at 11407.23,4087.64 h60
  text "X" at 12246.53,4087.64 h60
  text "ANSI IPC-6012 TYPE 3 CLASS 2" at 12433.48,4087.64 h60
  text "OTHER +/-" at 12433.46,3929.13 h60
  text "DRILLING:" at 11332.46,3790.64 h60
  text "REFERENCE:" at 11407.23,3673.64 h60
  text "X" at 12055.46,3673.64 h60
  text "AS SHOWN" at 12242.46,3673.64 h60
  text "X" at 12956.46,3673.64 h60
  text "NC_DRILL FILES" at 13093.46,3673.64 h60
  text "PTH MIN COPPER THICKNESS:" at 11407.23,3515.64 h60
  text "X" at 12757.46,3515.64 h60
  text "1MIL" at 12894.46,3515.64 h60
  text "OTHER" at 13391.46,3515.64 h60
  text "BOARD FINISH:" at 11332.46,3356.64 h60
  text "SILKSCREEN:" at 11487.68,3238.64 h60
  text "X" at 12436.46,3238.64 h60
  text "TOP" at 12562.46,3238.64 h60
  text "X" at 12946.46,3238.64 h60
  text "BOTTOM" at 13073.46,3238.64 h60
  text "SILKSCREEN COLOR:" at 11487.68,3071.64 h60
  text "X" at 12435.42,3071.64 h60
  text "WHITE" at 12562.46,3071.64 h60
  text "OTHER" at 13073.46,3071.64 h60
  text "SOLDER RESIST COLOR:" at 11487.68,2901.64 h60
  text "X" at 12055.42,2742.44 h60
  text "GREEN" at 12182.46,2742.44 h60
  text "BLUE" at 12773.46,2742.44 h60
  text "OTHER" at 13311.46,2742.44 h60
  text "IMMERSION GOLD (ENIG)" at 12393.46,2553.92 h60
  text "ENEPIG" at 13731,2550.64 h60
  text "SURFACE FINISH:" at 11332.46,2549.64 h60
  text "X" at 12206.51,2549.64 h60
  text "IMM. TIN/SILVER OR EQUIV" at 11662,2392.64 h60
  text "OTHER" at 13093.46,2392.64 h60
  text "ARRAY/PANEL:" at 11332.46,2213.64 h60
  text "CUT AND TRIM PER MECH LAYER 1" at 12393.46,2209.35 h60
  text "N.C. ROUTE" at 12393.46,2057.64 h60
  text "X" at 13072.46,2057.64 h60
  text "V. SCORE" at 13259.46,2057.64 h60
  text "CERTIFICATION:" at 11332.46,1920.64 h60
  text "MATERIALS AND WORKMANSHIP FOR ALL PCBS" at 12057.46,1920.64 h60
  text "TO MEET OR EXCEED THE REQUIREMENTS OF:" at 12057.46,1822.64 h60
  text "X" at 11683.96,1686.13 h60
  text "ANSI IPC-A-600F CLASS ->" at 11822.96,1686.13 h60
  text "X" at 13462.02,1686.13 h60
  text "2" at 13580.96,1686.14 h60
  text "1" at 13265.96,1684.64 h60
  text "3" at 13934.96,1684.64 h60
  text "X" at 11686.02,1526.64 h60
  text "UL 94V-0" at 11822.96,1526.64 h60
  text "X" at 12498.02,1526.64 h60
  text "RoHS" at 12634.96,1526.64 h60
  text "OTHER" at 13279.36,1526.64 h60
  text "PER ORDER" at 13676.42,1526.64 h60
  text "ADDITIONAL REQUIREMENTS:" at 11332.46,1385.64 h60
  text "MICROSECTION:" at 11407.23,1270.64 h60
  text "YES" at 12312.96,1270.64 h60
  text "REQUIRED" at 13174.46,1114.49 h60
  text "BARE BOARD ELEC. TEST:" at 11407.23,1111.64 h60
  text "NONE" at 12712.96,1111.64 h60
  text "X" at 13047.46,1111.64 h60
  text "PER ORDER" at 13766.46,1111.64 h60
  text "MANUFACTURER'S UL:" at 11407.23,954.64 h60
  text "RAIL" at 12572.96,950.35 h60
  text "METAL" at 13064.77,950.35 h60
  text "X" at 13440,950 h60
  text "SILK" at 13576.46,950.35 h60
  text ".Layer_Name" at 577,-858.49 h60
M11 Gerber Information:
  text "ALL ARTWORK VIEWED FROM TOP SIDE" at -228.5,-655.67 h60
  text "BOARD #:" at 2248,-655.67 h60
  text ".PRJ_Number" at 2793.5,-655.67 h60
  text "REV:" at 3638,-655.67 h60
  text ".PCB_Rev" at 3929.5,-655.67 h60
  text "SVN REV:" at 4476,-655.67 h60
  text ".VersionControl_RevNumber" at 4982,-655.67 h60
  text "LAYER NAME =" at -228.5,-858.49 h60
  text "TID #:" at 2248,-859 h60
  text ".TID" at 2793.5,-859 h60
  text "PLOT NAME =" at -228.5,-1064.34 h60
  text ".plot_File_Name" at 577,-1064.34 h60
  text "GENERATED    :" at 2250,-1064.34 h60
  text ".Print_Date" at 3119.5,-1064.34 h60
  text ".Print_Time" at 3848.5,-1064.34 h60
  text "TEXAS INSTRUMENTS" at 5113,-1064.34 h60
M12 Stackup:
  text ".Layer_Name" at 577,-858.49 h60
M13 Component Bodies Top:
  text ".Layer_Name" at 577,-858.49 h60
M14 Component Bodies Bottom:
  text ".Layer_Name" at 577,-858.49 h60
M15 Courtyards Top:
  text ".Layer_Name" at 577,-858.49 h60
M16 Courtyards Bottom:
  text ".Layer_Name" at 577,-858.49 h60
Drill Drawing:
  circle w10: c4214,6682.03 r27.63
  circle w10: c4214,6184.75 r16.58
  circle w10: c4214,6184.75 r27.63
  lines w10: 4186.37,6281.44 4186.37,6295.25 4200.18,6309.07 4186.37,6322.88 4186.37,6336.69 4200.18,6336.69 4214,6322.88 4227.81,6336.69 4241.62,6336.69 4241.62,6322.88 4227.81,6309.07 4241.62,6295.25 4241.62,6281.44 4227.81,6281.44 4214,6295.25 4200.18,6281.44 4186.37,6281.44 ; 4186.37,6461.01 4241.62,6461.01 4214,6405.76 4186.37,6461.01 ; 4186.37,6543.89 4200.18,6543.89 4214,6530.08 4227.81,6543.89 4241.62,6543.89 4227.81,6557.71 4241.62,6571.52 4227.81,6571.52 4214,6585.33 4200.18,6571.52 4186.37,6571.52 4200.18,6557.71 4186.37,6543.89 ; 4186.37,6778.72 4241.62,6778.72 4241.62,6833.97 4186.37,6833.97 4186.37,6778.72 ; 4186.37,6958.29 4241.62,6958.29 4214,6903.04 4186.37,6958.29 ; 4186.37,7054.99 4214,7027.36 4241.62,7054.99 4214,7082.61 4186.37,7054.99 ; 4186.37,7151.68 4214,7165.49 4241.62,7151.68 4227.81,7179.31 4241.62,7206.93 4214,7193.12 4186.37,7206.93 4200.18,7179.31 4186.37,7151.68 ; 4186.37,7276 4241.62,7276 4241.62,7331.25 4186.37,7331.25 4186.37,7276 ; 4186.37,7414.13 4200.18,7414.13 4214,7400.32 4227.81,7414.13 4241.62,7414.13 4227.81,7427.95 4241.62,7441.76 4227.81,7441.76 4214,7455.57 4200.18,7441.76 4186.37,7441.76 4200.18,7427.95 4186.37,7414.13 ; 4197.42,6449.96 4230.57,6449.96 4214,6416.81 4197.42,6449.96 ; 4197.42,6549.42 4205.71,6549.42 4214,6541.13 4222.28,6549.42 4230.57,6549.42 4222.28,6557.71 4230.57,6565.99 4222.28,6565.99 4214,6574.28 4205.71,6565.99 4197.42,6565.99 4205.71,6557.71 4197.42,6549.42 ; 4197.42,6789.77 4230.57,6789.77 4230.57,6822.92 4197.42,6822.92 4197.42,6789.77
  lines w12: 4136.28,6119.82 6114.3,6119.82 ; 4136.28,7487.34 6114.3,7487.34 ; 4474.14,5995.5 4474.14,7611.66 ; 4806.14,5995.5 4806.14,7611.66 ; 5442.7,5995.5 5442.7,7611.66 ; 5701.84,5995.5 5701.84,7611.66 ; 4136.28,5995.5 6114.3,5995.5 6114.3,7611.66 4136.28,7611.66 4136.28,5995.5
  text "Symbol" at 4210.87,7524.64 h72
  text "Quantity" at 4511.44,7524.64 h72
  text "Finished Hole Size" at 4843.44,7524.64 h72
  text "Plated" at 5480,7524.64 h72
  text "Hole Type" at 5739.14,7524.64 h72
  text "5" at 4511.44,7400.32 h60
  text "7,87mil (0,200mm)" at 4843.44,7400.32 h60
  text "PTH" at 5480,7400.32 h60
  text "Round" at 5739.14,7400.32 h60
  text "201" at 4511.44,7276 h60
  text "12,00mil (0,305mm)" at 4843.44,7276 h60
  text "PTH" at 5480,7276 h60
  text "Round" at 5739.14,7276 h60
  text "24" at 4511.44,7151.68 h60
  text "19,69mil (0,500mm)" at 4843.44,7151.68 h60
  text "PTH" at 5480,7151.68 h60
  text "Round" at 5739.14,7151.68 h60
  text "17" at 4511.44,7027.36 h60
  text "20,00mil (0,508mm)" at 4843.44,7027.36 h60
  text "PTH" at 5480,7027.36 h60
  text "Round" at 5739.14,7027.36 h60
  text "2" at 4511.44,6903.04 h60
  text "31,00mil (0,787mm)" at 4843.44,6903.04 h60
  text "PTH" at 5480,6903.04 h60
  text "Round" at 5739.14,6903.04 h60
  text "3" at 4511.44,6778.72 h60
  text "37,99mil (0,965mm)" at 4843.44,6778.72 h60
  text "PTH" at 5480,6778.72 h60
  text "Round" at 5739.14,6778.72 h60
  text "3" at 4511.44,6654.4 h60
  text "39,37mil (1,000mm)" at 4843.44,6654.4 h60
  text "PTH" at 5480,6654.4 h60
  text "Round" at 5739.14,6654.4 h60
  text "22" at 4511.44,6530.08 h60
  text "40,00mil (1,016mm)" at 4843.44,6530.08 h60
  text "PTH" at 5480,6530.08 h60
  text "Round" at 5739.14,6530.08 h60
  text "92" at 4511.44,6405.76 h60
  text "40,16mil (1,020mm)" at 4843.44,6405.76 h60
  text "PTH" at 5480,6405.76 h60
  text "Round" at 5739.14,6405.76 h60
  text "14" at 4511.44,6281.44 h60
  text "47,24mil (1,200mm)" at 4843.44,6281.44 h60
  text "PTH" at 5480,6281.44 h60
  text "Round" at 5739.14,6281.44 h60
  text "4" at 4511.44,6157.12 h60
  text "137,80mil (3,500mm)" at 4843.44,6157.12 h60
  text "PTH" at 5480,6157.12 h60
  text "Round" at 5739.14,6157.12 h60
  text "387 Total" at 4511.44,6032.8 h60
  text ".Layer_Name" at 577,-858.49 h60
